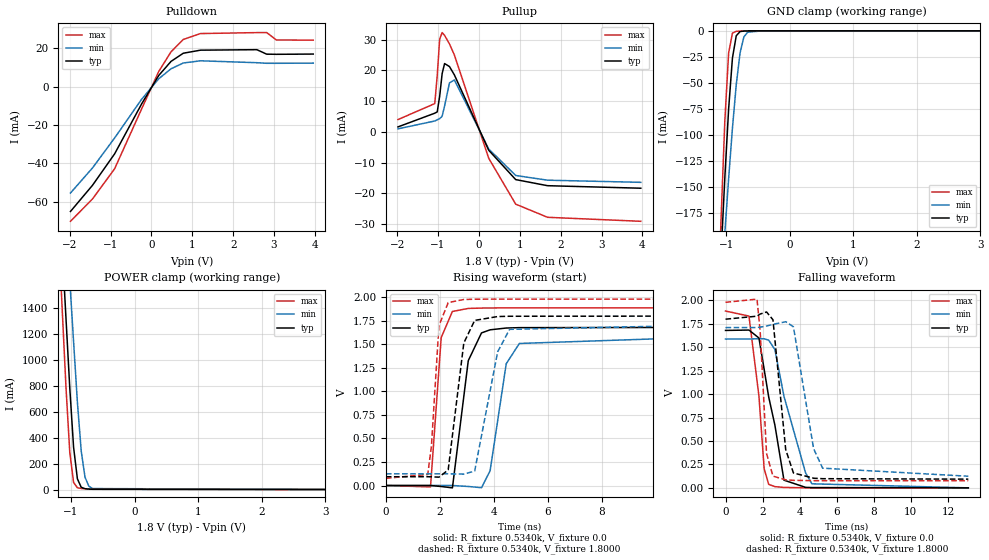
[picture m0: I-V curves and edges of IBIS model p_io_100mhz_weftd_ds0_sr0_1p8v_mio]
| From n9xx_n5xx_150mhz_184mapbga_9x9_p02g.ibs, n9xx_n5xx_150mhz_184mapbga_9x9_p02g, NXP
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[Model] p_io_100mhz_weftd_ds0_sr0_1p8v_mio
|   Model p_io_100mhz_weftd_ds0_sr0_1p8v_mio
| This model was characterised for following simulation conditions:
| External (pad) voltage:
|   - Typ: 1.8V,   - Min: 1.71V,   - Max: 1.98V
| Library cells for typ/min/max conditions are connected as defined below:
|  pad - External Pad
|  ipp_do_lv - Core Input
|  ipp_obe_lv - Output Buffer Enable
|  IOGC - NC
|  REFH3V3 - REFH3V3
|  REFL3V3 - REFL3V3
|  ZI - NC
|  abut_ncal_vddio[1] - vssio vddio vddio
|  abut_ncal_vddio[2] - vddio vddio vssio
|  abut_ncal_vddio[3] - vddio
|  abut_ncal_vddio[4] - vssio vddio vddio
|  abut_ncal_vddio[5] - vddio vddio vssio
|  abut_ncal_vddio[6] - vddio
|  abut_pcal_vddio[1] - vssio
|  abut_pcal_vddio[2] - vddio vssio vddio
|  abut_pcal_vddio[3] - vssio
|  abut_pcal_vddio[4] - vssio
|  abut_pcal_vddio[5] - vddio vssio vddio
|  abut_pcal_vddio[6] - vssio
|  ipp_do_1p8v - ipp_do_1p8v
|  ipp_dse_lv - 0
|  ipp_eftd_lv - NC
|  ipp_ina_mux_vddio - NC
|  ipp_ina_mux_vddio[0] - NC
|  ipp_ina_mux_vddio[1] - NC
|  ipp_ina_r0_vddio - NC
|  ipp_ina_r0a_vddio - NC
|  ipp_ina_r0b_vddio - NC
|  ipp_ina_r0c_vddio - NC
|  ipp_ina_r0d_vddio - NC
|  ipp_ina_r0e_vddio - NC
|  ipp_ina_r0f_vddio - NC
|  ipp_ina_r300_vddio - NC
|  ipp_ina_r300a_vddio - NC
|  ipp_ina_r300b_vddio - NC
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Model_type I/O
Polarity   Non-Inverting
Enable   Active-High
Vinl =   0.5400V
Vinh =   1.2600V
Vmeas =  0.9000V
Cref =   30.0000pF
Rref =   1.0000M
Vref =   1.8000V
C_comp   1.4209pF   1.3571pF   1.5007pF
|C_comp_pullup   0.7311pF   0.7578pF   0.7052pF
|C_comp_pulldown   0.6120pF   0.6628pF   0.5710pF
[Model Spec]
| variable   typ   min   max
Vinh   1.2600V   1.1970V   1.3860V
Vinl   0.5400V   0.5130V   0.5940V
[Temperature Range]   25.0000   0.1250k   -40.0000
[Voltage Range]   1.8000V   1.7100V   1.9800V
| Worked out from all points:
|   slope of the pulldown table from 0 to 0.27 V, typ, clamps not added: 32.1 ohm
|   slope of the pullup table from 0 to 0.27 V, typ, clamps not added: 40.9 ohm
|   GND clamp passes 1 mA (typ) near -0.78 V on its own axis
|   POWER clamp passes 1 mA (typ) near -0.56 V on its own axis
|   rising waveform, R_fixture 0.5340k, V_fixture 0.0: 20-80 % time 375ps typ, 478ps min, 240ps max; typ from 0 V to 1.68 V
|   rising waveform, R_fixture 0.5340k, V_fixture 1.8000: 20-80 % time 383ps typ, 516ps min, 234ps max; typ from 0.093 V to 1.8 V
|   falling waveform, R_fixture 0.5340k, V_fixture 0.0: 20-80 % time 874ps typ, 1.25ns min, 522ps max; typ from 1.68 V to 0 V
|   falling waveform, R_fixture 0.5340k, V_fixture 1.8000: 20-80 % time 429ps typ, 647ps min, 286ps max; typ from 1.8 V to 0.093 V
[Pulldown]
|Voltage   I(typ)   I(min)   I(max)
-1.98V    -65.1mA    -55.47mA   -70.23mA
-1.44V    -51.41mA   -42.35mA   -58.53mA
-900mV    -35.03mA   -26.74mA   -42.82mA
-240mV    -8.989mA   -6.551mA   -11.62mA
180mV     5.908mA    4.185mA    8mA
480mV     13.23mA    9.376mA    18.23mA
780mV     17.5mA     12.4mA     24.7mA
1.2V      19.1mA     13.55mA    27.77mA
2.58V     19.36mA    12.56mA    28.27mA
2.82V     17.02mA    12.25mA    28.29mA
3.06V     16.94mA    12.25mA    24.4mA
3.96V     17.07mA    12.34mA    24.35mA
[Pullup]
|Voltage   I(typ)   I(min)   I(max)
-1.98V    1.629mA    999.6uA    4.015mA
-1.08V    6.088mA    3.551mA    9.212mA
-1.02V    6.511mA    3.928mA    18.3mA
-960mV    11.61mA    4.321mA    30.17mA
-900mV    18.93mA    5.074mA    32.31mA
-840mV    22.23mA    8.425mA    31.4mA
-720mV    21.25mA    15.95mA    28.6mA
-600mV    18.53mA    16.91mA    25.01mA
240mV     -5.966mA   -5.551mA   -8.574mA
900mV     -15.51mA   -14.17mA   -23.49mA
1.68V     -17.49mA   -15.7mA    -27.77mA
3.96V     -18.31mA   -16.4mA    -29.07mA
[GND_clamp]
|Voltage   I(typ)   I(min)   I(max)
-1.98V    -1.543A    -1.201A    -2.023A
-1.14V    -295.8mA   -306.3mA   -290.9mA
-1.08V    -216.4mA   -249.6mA   -182.7mA
-1.02V    -141.5mA   -194.6mA   -86.96mA
-960mV    -75.17mA   -142.1mA   -21.27mA
-900mV    -26.1mA    -93.57mA   -2.196mA
-840mV    -4.74mA    -51.67mA   -453.8uA
-780mV    -724.6uA   -21.14mA   -264.4uA
-720mV    -210.5uA   -5.843mA   -181.4uA
-660mV    -110.6uA   -1.28mA    -117.6uA
-420mV    -5.355uA   -12.87uA   -3.465uA
3.96V     0A         0A         0A
[POWER_clamp]
|Voltage   I(typ)   I(min)   I(max)
-1.98V    9.578A     9.289A     10.07A
-1.2V     2.41A      3.038A     2.007A
-1.14V    1.864A     2.561A     1.396A
-1.08V    1.321A     2.084A     791.3mA
-1.02V    783mA      1.609A     287.7mA
-960mV    325.3mA    1.137A     54.76mA
-900mV    82.69mA    671.2mA    14.16mA
-840mV    18.08mA    297mA      8.834mA
-780mV    6.944mA    95.27mA    6.398mA
-720mV    4.174mA    26.01mA    4.41mA
-660mV    2.65mA     7.951mA    2.754mA
3.96V     0A         0A         0A
[Ramp]
| variable   typ   min   max
dV/dt_r  1.0081/0.3746n   0.9531/0.4784n   1.1320/0.2401n
dV/dt_f  1.0242/0.4289n   0.9515/0.6473n   1.1422/0.2863n
R_load = 0.5340k
[Rising Waveform]
R_fixture= 0.5340k
V_fixture= 0.0
V_fixture_min= 0.0
V_fixture_max= 0.0
|time   V(typ)   V(min)   V(max)
0s        469.4pV    172.1nV    14.64pV
1.655ns   101.7uV    -83.16uV   -15.11mV
2.051ns   -10.72mV   283.9uV    1.571V
2.467ns   -24.98mV   136.5uV    1.849V
3.054ns   1.326V     -10.16mV   1.881V
3.544ns   1.621V     -23.5mV    1.885V
3.864ns   1.654V     156.7mV    1.886V
4.461ns   1.673V     1.294V     1.887V
4.948ns   1.677V     1.509V     1.887V
13.1ns    1.68V      1.588V     1.887V
[Rising Waveform]
R_fixture= 0.5340k
V_fixture= 1.8000
V_fixture_min= 1.7100
V_fixture_max= 1.9800
|time   V(typ)   V(min)   V(max)
0s        93mV       124mV      76.32mV
1.553ns   93.25mV    123.9mV    117.6mV
1.688ns   92.31mV    123.9mV    416.6mV
1.968ns   88.84mV    124.2mV    1.699V
2.31ns    165.8mV    124.1mV    1.943V
2.889ns   1.514V     121mV      1.976V
3.292ns   1.754V     153.6mV    1.979V
4.142ns   1.795V     1.419V     1.98V
4.583ns   1.798V     1.659V     1.98V
13.1ns    1.8V       1.71V      1.98V
[Falling Waveform]
R_fixture= 0.5340k
V_fixture= 0.0
V_fixture_min= 0.0
V_fixture_max= 0.0
|time   V(typ)   V(min)   V(max)
0s        1.68V      1.588V     1.887V
1.266ns   1.684V     1.588V     1.833V
1.804ns   1.599V     1.592V     979.7mV
2.086ns   1.264V     1.591V     203.2mV
2.33ns    970.5mV    1.576V     37.35mV
2.664ns   670.3mV    1.476V     13.42mV
3.154ns   82.31mV    977.6mV    4.512mV
4.319ns   5.34mV     161mV      586.8uV
4.662ns   3.287mV    43.22mV    371.5uV
13.1ns    44.97uV    87.52uV    28.02uV
[Falling Waveform]
R_fixture= 0.5340k
V_fixture= 1.8000
V_fixture_min= 1.7100
V_fixture_max= 1.9800
|time   V(typ)   V(min)   V(max)
0s        1.8V       1.71V      1.98V
1.7ns     1.832V     1.711V     2.014V
1.872ns   1.855V     1.715V     1.669V
2.215ns   1.877V     1.727V     366.2mV
2.56ns    1.794V     1.745V     125.2mV
3.247ns   409.9mV    1.773V     85.73mV
3.664ns   159.1mV    1.719V     80.33mV
4.755ns   102.9mV    417.3mV    76.96mV
5.241ns   97.85mV    210.1mV    76.68mV
13.1ns    93.06mV    124.1mV    76.36mV
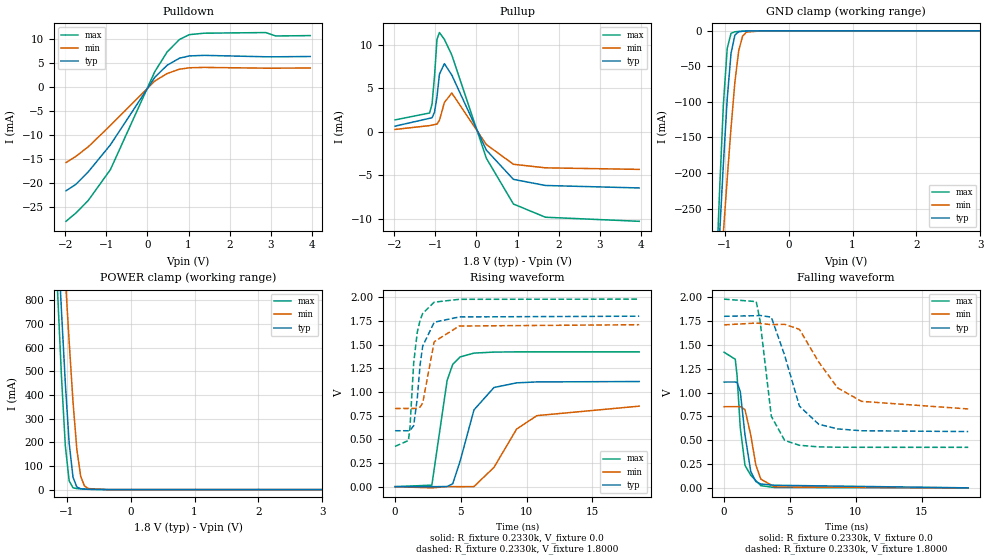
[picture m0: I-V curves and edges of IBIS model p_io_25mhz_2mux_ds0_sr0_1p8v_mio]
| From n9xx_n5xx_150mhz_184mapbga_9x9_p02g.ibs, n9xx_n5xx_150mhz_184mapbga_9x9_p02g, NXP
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[Model] p_io_25mhz_2mux_ds0_sr0_1p8v_mio
|   Model p_io_25mhz_2mux_ds0_sr0_1p8v_mio
| This model was characterised for following simulation conditions:
| External (pad) voltage:
|   - Typ: 1.8V,   - Min: 1.71V,   - Max: 1.98V
| Library cells for typ/min/max conditions are connected as defined below:
|  pad - External Pad
|  ipp_do_lv - Core Input
|  ipp_obe_lv - Output Buffer Enable
|  IOGC - NC
|  REFH3V3 - REFH3V3
|  REFL3V3 - REFL3V3
|  ZI - NC
|  abut_ncal_vddio[1] - vssio vddio vddio
|  abut_ncal_vddio[2] - vddio vddio vssio
|  abut_ncal_vddio[3] - vddio
|  abut_ncal_vddio[4] - vssio vddio vddio
|  abut_ncal_vddio[5] - vddio vddio vssio
|  abut_ncal_vddio[6] - vddio
|  abut_pcal_vddio[1] - vssio
|  abut_pcal_vddio[2] - vddio vssio vddio
|  abut_pcal_vddio[3] - vssio
|  abut_pcal_vddio[4] - vssio
|  abut_pcal_vddio[5] - vddio vssio vddio
|  abut_pcal_vddio[6] - vssio
|  ipp_do_1p8v - ipp_do_1p8v
|  ipp_dse_lv - 0
|  ipp_eftd_lv - NC
|  ipp_ina_mux_vddio - NC
|  ipp_ina_mux_vddio[0] - NC
|  ipp_ina_mux_vddio[1] - NC
|  ipp_ina_r0_vddio - NC
|  ipp_ina_r0a_vddio - NC
|  ipp_ina_r0b_vddio - NC
|  ipp_ina_r0c_vddio - NC
|  ipp_ina_r0d_vddio - NC
|  ipp_ina_r0e_vddio - NC
|  ipp_ina_r0f_vddio - NC
|  ipp_ina_r300_vddio - NC
|  ipp_ina_r300a_vddio - NC
|  ipp_ina_r300b_vddio - NC
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Model_type I/O
Polarity   Non-Inverting
Enable   Active-High
Vinl =   0.5400V
Vinh =   1.2600V
Vmeas =  0.9000V
Cref =   30.0000pF
Rref =   1.0000M
Vref =   1.8000V
C_comp   1.3067pF   1.2540pF   1.3694pF
|C_comp_pullup   0.5686pF   0.5978pF   0.5418pF
|C_comp_pulldown   0.6638pF   0.6956pF   0.6389pF
[Model Spec]
| variable   typ   min   max
Vinh   1.2600V   1.1970V   1.3860V
Vinl   0.5400V   0.5130V   0.5940V
[Temperature Range]   25.0000   0.1250k   -40.0000
[Voltage Range]   1.8000V   1.7100V   1.9800V
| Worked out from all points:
|   slope of the pulldown table from 0 to 0.27 V, typ, clamps not added: 93.6 ohm
|   slope of the pullup table from 0 to 0.27 V, typ, clamps not added: 116 ohm
|   GND clamp passes 1 mA (typ) near -0.75 V on its own axis
|   POWER clamp passes 1 mA (typ) near -0.63 V on its own axis
|   rising waveform, R_fixture 0.2330k, V_fixture 0.0: 20-80 % time 1.45ns typ, 2.43ns min, 833ps max; typ from 0 V to 1.11 V
|   rising waveform, R_fixture 0.2330k, V_fixture 1.8000: 20-80 % time 594ps typ, 656ps min, 564ps max; typ from 0.59 V to 1.8 V
|   falling waveform, R_fixture 0.2330k, V_fixture 0.0: 20-80 % time 571ps typ, 672ps min, 509ps max; typ from 1.11 V to 0 V
|   falling waveform, R_fixture 0.2330k, V_fixture 1.8000: 20-80 % time 1.51ns typ, 2.64ns min, 803ps max; typ from 1.8 V to 0.591 V
[Pulldown]
|Voltage   I(typ)   I(min)   I(max)
-1.98V    -21.59mA   -15.72mA   -27.94mA
-1.74V    -20.25mA   -14.42mA   -26.22mA
-1.44V    -17.66mA   -12.45mA   -23.61mA
-900mV    -12.03mA   -7.992mA   -17.18mA
180mV     2.026mA    1.252mA    3.209mA
480mV     4.533mA    2.805mA    7.304mA
780mV     5.999mA    3.712mA    9.89mA
1.02V     6.468mA    4.005mA    10.9mA
1.38V     6.587mA    4.078mA    11.2mA
2.88V     6.293mA    3.922mA    11.33mA
3.12V     6.289mA    3.924mA    10.62mA
3.96V     6.35mA     3.959mA    10.7mA
[Pullup]
|Voltage   I(typ)   I(min)   I(max)
-1.98V    644.9uA    266.3uA    1.361mA
-1.14V    1.542mA    707.2uA    2.153mA
-1.08V    1.604mA    764.5uA    3.171mA
-1.02V    2.234mA    824.1uA    6.358mA
-960mV    4.021mA    885.3uA    10.59mA
-900mV    6.607mA    1.315mA    11.37mA
-780mV    7.807mA    3.354mA    10.59mA
-600mV    6.505mA    4.443mA    8.805mA
240mV     -2.097mA   -1.459mA   -3.022mA
900mV     -5.454mA   -3.726mA   -8.28mA
1.68V     -6.156mA   -4.132mA   -9.795mA
3.96V     -6.438mA   -4.31mA    -10.26mA
[GND_clamp]
|Voltage   I(typ)   I(min)   I(max)
-1.98V    -2A        -1.65A     -2.499A
-1.14V    -394mA     -441.5mA   -363.8mA
-1.08V    -288.3mA   -361.7mA   -226.5mA
-1.02V    -187.2mA   -283.6mA   -103.8mA
-960mV    -95.65mA   -208mA     -24.73mA
-900mV    -31.48mA   -136.2mA   -3.446mA
-840mV    -6.013mA   -72.18mA   -1.335mA
-780mV    -1.302mA   -27.91mA   -907.3uA
-720mV    -579.6uA   -7.635mA   -620.4uA
-660mV    -347.7uA   -1.81mA    -390uA
-420mV    -12.74uA   -30.23uA   -7.287uA
3.96V     0A         0A         0A
[POWER_clamp]
|Voltage   I(typ)   I(min)   I(max)
-1.98V    5.618A     5.349A     6.084A
-1.14V    1.071A     1.443A     829.6mA
-1.08V    754.2mA    1.168A     476.4mA
-1.02V    449mA      895.6mA    184.6mA
-960mV    195.8mA    625.5mA    36.76mA
-900mV    52.43mA    371.1mA    7.779mA
-840mV    10.73mA    170.2mA    4.41mA
-780mV    3.609mA    56.22mA    3.161mA
-720mV    2.066mA    15.04mA    2.177mA
-660mV    1.299mA    4.297mA    1.362mA
-360mV    4.834uA    27.3uA     1.2uA
3.96V     0A         0A         0A
[Ramp]
| variable   typ   min   max
dV/dt_r  0.6658/1.4492n   0.5100/2.4251n   0.8537/0.8330n
dV/dt_f  0.7257/1.5102n   0.5293/2.6446n   0.9328/0.8032n
R_load = 0.2330k
[Rising Waveform]
R_fixture= 0.2330k
V_fixture= 0.0
V_fixture_min= 0.0
V_fixture_max= 0.0
|time   V(typ)   V(min)   V(max)
0s        586.1pV    202.5nV    16.24pV
2.795ns   -85.97uV   -12.58mV   16.06mV
3.955ns   1.317mV    419.6uV    1.121V
4.382ns   30.46mV    829.6uV    1.291V
4.948ns   272mV      154.2uV    1.37V
5.996ns   810.5mV    1.17mV     1.41V
7.517ns   1.047V     204.1mV    1.421V
9.234ns   1.096V     607.6mV    1.423V
10.78ns   1.106V     750.1mV    1.423V
18.55ns   1.11V      850.1mV    1.423V
[Rising Waveform]
R_fixture= 0.2330k
V_fixture= 1.8000
V_fixture_min= 1.7100
V_fixture_max= 1.9800
|time   V(typ)   V(min)   V(max)
0s        590.5mV    825.5mV    425.3mV
1.015ns   590.4mV    825.6mV    487.4mV
1.131ns   591.3mV    825.6mV    619.4mV
1.413ns   643.9mV    825.6mV    1.303V
1.687ns   930.3mV    826.4mV    1.629V
1.906ns   1.292V     841.7mV    1.759V
2.101ns   1.484V     883.5mV    1.829V
2.974ns   1.736V     1.53V      1.948V
4.88ns    1.792V     1.696V     1.978V
18.55ns   1.8V       1.71V      1.98V
[Falling Waveform]
R_fixture= 0.2330k
V_fixture= 0.0
V_fixture_min= 0.0
V_fixture_max= 0.0
|time   V(typ)   V(min)   V(max)
0s        1.11V      851.6mV    1.423V
851.4ps   1.111V     851.6mV    1.349V
987.8ps   1.105V     851.6mV    1.177V
1.23ns    1.012V     853.3mV    632.6mV
1.588ns   556.7mV    821.3mV    237mV
2.028ns   171.6mV    553.9mV    131.8mV
2.413ns   66.38mV    239.2mV    76.44mV
2.793ns   40.27mV    91.14mV    23mV
3.824ns   27.36mV    10.55mV    3.971mV
18.55ns   311.9nV    11.36uV    55.71nV
[Falling Waveform]
R_fixture= 0.2330k
V_fixture= 1.8000
V_fixture_min= 1.7100
V_fixture_max= 1.9800
|time   V(typ)   V(min)   V(max)
0s        1.8V       1.71V      1.98V
2.443ns   1.806V     1.729V     1.954V
2.729ns   1.809V     1.725V     1.758V
3.59ns    1.791V     1.712V     751mV
4.601ns   1.391V     1.716V     498.2mV
5.726ns   857.5mV    1.663V     446.5mV
7.189ns   667.1mV    1.32V      429.9mV
8.633ns   618.5mV    1.048V     426.5mV
10.45ns   599mV      907.3mV    425.5mV
18.55ns   590.6mV    827.9mV    425.3mV
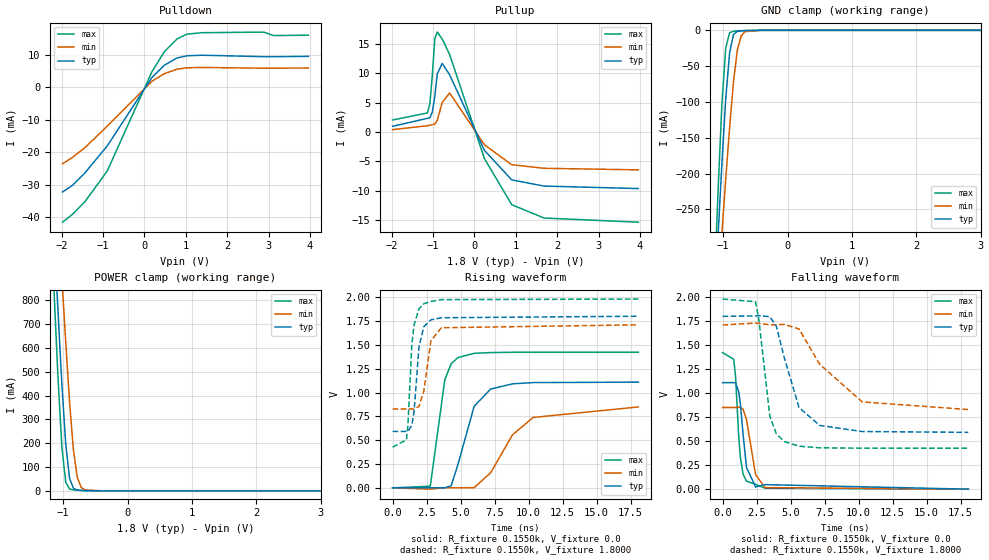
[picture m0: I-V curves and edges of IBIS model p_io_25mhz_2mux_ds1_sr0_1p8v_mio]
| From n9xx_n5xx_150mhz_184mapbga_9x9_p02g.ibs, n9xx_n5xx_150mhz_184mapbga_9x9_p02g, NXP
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[Model] p_io_25mhz_2mux_ds1_sr0_1p8v_mio
|   Model p_io_25mhz_2mux_ds1_sr0_1p8v_mio
| This model was characterised for following simulation conditions:
| External (pad) voltage:
|   - Typ: 1.8V,   - Min: 1.71V,   - Max: 1.98V
| Library cells for typ/min/max conditions are connected as defined below:
|  pad - External Pad
|  ipp_do_lv - Core Input
|  ipp_obe_lv - Output Buffer Enable
|  IOGC - NC
|  REFH3V3 - REFH3V3
|  REFL3V3 - REFL3V3
|  ZI - NC
|  abut_ncal_vddio[1] - vssio vddio vddio
|  abut_ncal_vddio[2] - vddio vddio vssio
|  abut_ncal_vddio[3] - vddio
|  abut_ncal_vddio[4] - vssio vddio vddio
|  abut_ncal_vddio[5] - vddio vddio vssio
|  abut_ncal_vddio[6] - vddio
|  abut_pcal_vddio[1] - vssio
|  abut_pcal_vddio[2] - vddio vssio vddio
|  abut_pcal_vddio[3] - vssio
|  abut_pcal_vddio[4] - vssio
|  abut_pcal_vddio[5] - vddio vssio vddio
|  abut_pcal_vddio[6] - vssio
|  ipp_do_1p8v - ipp_do_1p8v
|  ipp_dse_lv - vdd_lv
|  ipp_eftd_lv - NC
|  ipp_ina_mux_vddio - NC
|  ipp_ina_mux_vddio[0] - NC
|  ipp_ina_mux_vddio[1] - NC
|  ipp_ina_r0_vddio - NC
|  ipp_ina_r0a_vddio - NC
|  ipp_ina_r0b_vddio - NC
|  ipp_ina_r0c_vddio - NC
|  ipp_ina_r0d_vddio - NC
|  ipp_ina_r0e_vddio - NC
|  ipp_ina_r0f_vddio - NC
|  ipp_ina_r300_vddio - NC
|  ipp_ina_r300a_vddio - NC
|  ipp_ina_r300b_vddio - NC
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Model_type I/O
Polarity   Non-Inverting
Enable   Active-High
Vinl =   0.5400V
Vinh =   1.2600V
Vmeas =  0.9000V
Cref =   30.0000pF
Rref =   1.0000M
Vref =   1.8000V
C_comp   1.3067pF   1.2540pF   1.3694pF
|C_comp_pullup   0.5683pF   0.5975pF   0.5415pF
|C_comp_pulldown   0.6642pF   0.6959pF   0.6393pF
[Model Spec]
| variable   typ   min   max
Vinh   1.2600V   1.1970V   1.3860V
Vinl   0.5400V   0.5130V   0.5940V
[Temperature Range]   25.0000   0.1250k   -40.0000
[Voltage Range]   1.8000V   1.7100V   1.9800V
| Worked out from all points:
|   slope of the pulldown table from 0 to 0.27 V, typ, clamps not added: 62.4 ohm
|   slope of the pullup table from 0 to 0.27 V, typ, clamps not added: 77.5 ohm
|   GND clamp passes 1 mA (typ) near -0.75 V on its own axis
|   POWER clamp passes 1 mA (typ) near -0.63 V on its own axis
|   rising waveform, R_fixture 0.1550k, V_fixture 0.0: 20-80 % time 1.35ns typ, 2.38ns min, 760ps max; typ from 0 V to 1.11 V
|   rising waveform, R_fixture 0.1550k, V_fixture 1.8000: 20-80 % time 422ps typ, 518ps min, 382ps max; typ from 0.592 V to 1.8 V
|   falling waveform, R_fixture 0.1550k, V_fixture 0.0: 20-80 % time 453ps typ, 574ps min, 375ps max; typ from 1.11 V to 0 V
|   falling waveform, R_fixture 0.1550k, V_fixture 1.8000: 20-80 % time 1.46ns typ, 2.58ns min, 755ps max; typ from 1.8 V to 0.592 V
[Pulldown]
|Voltage   I(typ)   I(min)   I(max)
-1.98V    -32.19mA   -23.51mA   -41.49mA
-1.74V    -30.15mA   -21.53mA   -39.06mA
-1.44V    -26.33mA   -18.56mA   -35.19mA
-900mV    -18.01mA   -11.95mA   -25.73mA
180mV     3.037mA    1.878mA    4.81mA
480mV     6.798mA    4.207mA    10.95mA
780mV     8.998mA    5.569mA    14.83mA
1.02V     9.703mA    6.009mA    16.35mA
1.38V     9.882mA    6.118mA    16.81mA
2.88V     9.44mA     5.884mA    17mA
3.12V     9.433mA    5.887mA    15.93mA
3.96V     9.527mA    5.94mA     16.05mA
[Pullup]
|Voltage   I(typ)   I(min)   I(max)
-1.98V    966.3uA    399.3uA    2.044mA
-1.14V    2.321mA    1.063mA    3.243mA
-1.08V    2.416mA    1.15mA     4.764mA
-1.02V    3.358mA    1.24mA     9.557mA
-960mV    6.04mA     1.332mA    15.9mA
-900mV    9.92mA     1.974mA    17.06mA
-780mV    11.71mA    5.034mA    15.89mA
-600mV    9.758mA    6.666mA    13.21mA
240mV     -3.146mA   -2.189mA   -4.533mA
900mV     -8.184mA   -5.592mA   -12.42mA
1.68V     -9.239mA   -6.201mA   -14.7mA
3.96V     -9.667mA   -6.471mA   -15.41mA
[GND_clamp]
|Voltage   I(typ)   I(min)   I(max)
-1.98V    -2A        -1.65A     -2.499A
-1.14V    -394mA     -441.5mA   -363.8mA
-1.08V    -288.3mA   -361.7mA   -226.5mA
-1.02V    -187.2mA   -283.6mA   -103.8mA
-960mV    -95.65mA   -208mA     -24.73mA
-900mV    -31.48mA   -136.2mA   -3.446mA
-840mV    -6.013mA   -72.18mA   -1.335mA
-780mV    -1.302mA   -27.91mA   -907.3uA
-720mV    -579.6uA   -7.636mA   -620.4uA
-660mV    -347.7uA   -1.81mA    -390uA
-420mV    -12.74uA   -30.28uA   -7.287uA
3.96V     0A         0A         0A
[POWER_clamp]
|Voltage   I(typ)   I(min)   I(max)
-1.98V    5.618A     5.349A     6.084A
-1.14V    1.071A     1.443A     829.6mA
-1.08V    754.2mA    1.168A     476.4mA
-1.02V    449mA      895.6mA    184.6mA
-960mV    195.8mA    625.5mA    36.76mA
-900mV    52.43mA    371.1mA    7.779mA
-840mV    10.73mA    170.2mA    4.41mA
-780mV    3.609mA    56.22mA    3.161mA
-720mV    2.066mA    15.04mA    2.177mA
-660mV    1.299mA    4.297mA    1.362mA
-360mV    4.834uA    27.3uA     1.2uA
3.96V     0A         0A         0A
[Ramp]
| variable   typ   min   max
dV/dt_r  0.6652/1.3475n   0.5092/2.3844n   0.8531/0.7600n
dV/dt_f  0.7249/1.4571n   0.5285/2.5847n   0.9321/0.7551n
R_load = 0.1550k
[Rising Waveform]
R_fixture= 0.1550k
V_fixture= 0.0
V_fixture_min= 0.0
V_fixture_max= 0.0
|time   V(typ)   V(min)   V(max)
0s        408.8pV    135.5nV    11.61pV
2.774ns   1.162mV    -13.58mV   18.06mV
3.836ns   232.2uV    936.4uV    1.132V
4.306ns   22.02mV    1.123mV    1.302V
4.813ns   249.4mV    545.3uV    1.367V
5.996ns   855.7mV    2.319mV    1.411V
7.206ns   1.036V     158mV      1.419V
8.808ns   1.091V     555.5mV    1.422V
10.33ns   1.104V     738.5mV    1.422V
18.06ns   1.109V     848.7mV    1.422V
[Rising Waveform]
R_fixture= 0.1550k
V_fixture= 1.8000
V_fixture_min= 1.7100
V_fixture_max= 1.9800
|time   V(typ)   V(min)   V(max)
0s        591.8mV    826.8mV    426.5mV
1.021ns   591.5mV    826.8mV    503.4mV
1.129ns   592.9mV    826.8mV    657.1mV
1.413ns   655.9mV    826.8mV    1.495V
1.578ns   797.1mV    826.6mV    1.707V
1.944ns   1.482V     854.9mV    1.879V
2.298ns   1.69V      1.015V     1.931V
2.82ns    1.762V     1.544V     1.955V
3.586ns   1.784V     1.679V     1.974V
18.06ns   1.8V       1.71V      1.98V
[Falling Waveform]
R_fixture= 0.1550k
V_fixture= 0.0
V_fixture_min= 0.0
V_fixture_max= 0.0
|time   V(typ)   V(min)   V(max)
0s        1.109V     850.6mV    1.422V
816.9ps   1.11V      850.5mV    1.353V
951.9ps   1.107V     850.6mV    1.181V
1.186ns   1.016V     852.9mV    551.3mV
1.305ns   893.8mV    853.3mV    335.1mV
1.511ns   566.3mV    830.2mV    155.2mV
1.759ns   225.8mV    724.5mV    83.02mV
2.428ns   23.3mV     150mV      50.47mV
3.117ns   47.51mV    16.51mV    9.609mV
18.06ns   302.2nV    12.16uV    23.95nV
[Falling Waveform]
R_fixture= 0.1550k
V_fixture= 1.8000
V_fixture_min= 1.7100
V_fixture_max= 1.9800
|time   V(typ)   V(min)   V(max)
0s        1.8V       1.71V      1.98V
2.42ns    1.804V     1.73V      1.953V
2.668ns   1.808V     1.726V     1.766V
3.471ns   1.796V     1.712V     759.9mV
3.948ns   1.698V     1.713V     576.3mV
4.549ns   1.363V     1.716V     495.4mV
5.62ns    850.1mV    1.668V     447.4mV
7.136ns   663.5mV    1.301V     430.8mV
10.26ns   600.2mV    909.1mV    426.7mV
18.06ns   591.8mV    829.2mV    426.5mV
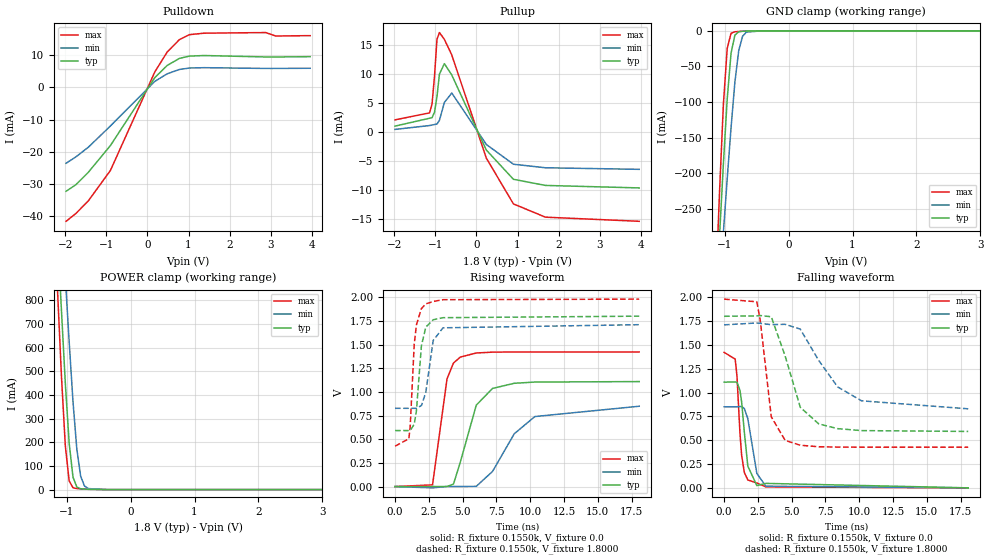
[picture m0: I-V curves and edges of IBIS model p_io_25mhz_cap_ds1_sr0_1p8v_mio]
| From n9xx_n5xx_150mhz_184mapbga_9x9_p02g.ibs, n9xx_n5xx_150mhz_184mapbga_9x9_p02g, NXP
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[Model] p_io_25mhz_cap_ds1_sr0_1p8v_mio
|   Model p_io_25mhz_cap_ds1_sr0_1p8v_mio
| This model was characterised for following simulation conditions:
| External (pad) voltage:
|   - Typ: 1.8V,   - Min: 1.71V,   - Max: 1.98V
| Library cells for typ/min/max conditions are connected as defined below:
|  pad - External Pad
|  ipp_do_lv - Core Input
|  ipp_obe_lv - Output Buffer Enable
|  IOGC - NC
|  REFH3V3 - REFH3V3
|  REFL3V3 - REFL3V3
|  ZI - NC
|  abut_ncal_vddio[1] - vssio vddio vddio
|  abut_ncal_vddio[2] - vddio vddio vssio
|  abut_ncal_vddio[3] - vddio
|  abut_ncal_vddio[4] - vssio vddio vddio
|  abut_ncal_vddio[5] - vddio vddio vssio
|  abut_ncal_vddio[6] - vddio
|  abut_pcal_vddio[1] - vssio
|  abut_pcal_vddio[2] - vddio vssio vddio
|  abut_pcal_vddio[3] - vssio
|  abut_pcal_vddio[4] - vssio
|  abut_pcal_vddio[5] - vddio vssio vddio
|  abut_pcal_vddio[6] - vssio
|  ipp_do_1p8v - ipp_do_1p8v
|  ipp_dse_lv - vdd_lv
|  ipp_eftd_lv - NC
|  ipp_ina_mux_vddio - NC
|  ipp_ina_mux_vddio[0] - NC
|  ipp_ina_mux_vddio[1] - NC
|  ipp_ina_r0_vddio - NC
|  ipp_ina_r0a_vddio - NC
|  ipp_ina_r0b_vddio - NC
|  ipp_ina_r0c_vddio - NC
|  ipp_ina_r0d_vddio - NC
|  ipp_ina_r0e_vddio - NC
|  ipp_ina_r0f_vddio - NC
|  ipp_ina_r300_vddio - NC
|  ipp_ina_r300a_vddio - NC
|  ipp_ina_r300b_vddio - NC
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Model_type I/O
Polarity   Non-Inverting
Enable   Active-High
Vinl =   0.5400V
Vinh =   1.2600V
Vmeas =  0.9000V
Cref =   30.0000pF
Rref =   1.0000M
Vref =   1.8000V
C_comp   1.3068pF   1.2541pF   1.3694pF
|C_comp_pullup   0.5693pF   0.5985pF   0.5425pF
|C_comp_pulldown   0.6508pF   0.6825pF   0.6258pF
[Model Spec]
| variable   typ   min   max
Vinh   1.2600V   1.1970V   1.3860V
Vinl   0.5400V   0.5130V   0.5940V
[Temperature Range]   25.0000   0.1250k   -40.0000
[Voltage Range]   1.8000V   1.7100V   1.9800V
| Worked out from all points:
|   slope of the pulldown table from 0 to 0.27 V, typ, clamps not added: 62.4 ohm
|   slope of the pullup table from 0 to 0.27 V, typ, clamps not added: 77.5 ohm
|   GND clamp passes 1 mA (typ) near -0.76 V on its own axis
|   POWER clamp passes 1 mA (typ) near -0.63 V on its own axis
|   rising waveform, R_fixture 0.1550k, V_fixture 0.0: 20-80 % time 1.35ns typ, 2.38ns min, 759ps max; typ from 0 V to 1.11 V
|   rising waveform, R_fixture 0.1550k, V_fixture 1.8000: 20-80 % time 423ps typ, 518ps min, 382ps max; typ from 0.592 V to 1.8 V
|   falling waveform, R_fixture 0.1550k, V_fixture 0.0: 20-80 % time 453ps typ, 574ps min, 375ps max; typ from 1.11 V to 0 V
|   falling waveform, R_fixture 0.1550k, V_fixture 1.8000: 20-80 % time 1.46ns typ, 2.58ns min, 755ps max; typ from 1.8 V to 0.592 V
[Pulldown]
|Voltage   I(typ)   I(min)   I(max)
-1.98V    -32.19mA   -23.51mA   -41.49mA
-1.74V    -30.15mA   -21.53mA   -39.06mA
-1.44V    -26.34mA   -18.56mA   -35.19mA
-900mV    -18.01mA   -11.95mA   -25.73mA
180mV     3.037mA    1.878mA    4.81mA
480mV     6.798mA    4.207mA    10.95mA
780mV     8.998mA    5.569mA    14.83mA
1.02V     9.704mA    6.009mA    16.35mA
1.38V     9.882mA    6.119mA    16.81mA
2.88V     9.44mA     5.884mA    17mA
3.12V     9.433mA    5.887mA    15.93mA
3.96V     9.528mA    5.94mA     16.05mA
[Pullup]
|Voltage   I(typ)   I(min)   I(max)
-1.98V    966.2uA    399.3uA    2.044mA
-1.14V    2.321mA    1.063mA    3.243mA
-1.08V    2.416mA    1.15mA     4.764mA
-1.02V    3.358mA    1.24mA     9.557mA
-960mV    6.04mA     1.332mA    15.9mA
-900mV    9.92mA     1.974mA    17.06mA
-780mV    11.71mA    5.034mA    15.89mA
-600mV    9.758mA    6.666mA    13.21mA
240mV     -3.146mA   -2.189mA   -4.533mA
900mV     -8.184mA   -5.592mA   -12.42mA
1.68V     -9.239mA   -6.201mA   -14.7mA
3.96V     -9.667mA   -6.471mA   -15.41mA
[GND_clamp]
|Voltage   I(typ)   I(min)   I(max)
-1.98V    -2A        -1.65A     -2.499A
-1.14V    -394mA     -441.5mA   -363.8mA
-1.08V    -288.3mA   -361.7mA   -226.5mA
-1.02V    -187.2mA   -283.6mA   -103.8mA
-960mV    -95.64mA   -207.9mA   -24.71mA
-900mV    -31.47mA   -136.2mA   -3.431mA
-840mV    -6.005mA   -72.18mA   -1.326mA
-780mV    -1.297mA   -27.91mA   -902.8uA
-720mV    -576.7uA   -7.632mA   -619.4uA
-660mV    -346.6uA   -1.808mA   -391.2uA
-420mV    -13.9uA    -31.16uA   -8.588uA
3.96V     0A         0A         0A
[POWER_clamp]
|Voltage   I(typ)   I(min)   I(max)
-1.98V    5.618A     5.349A     6.084A
-1.14V    1.071A     1.443A     829.6mA
-1.08V    754.2mA    1.168A     476.4mA
-1.02V    449mA      895.6mA    184.6mA
-960mV    195.8mA    625.5mA    36.79mA
-900mV    52.44mA    371.1mA    7.808mA
-840mV    10.74mA    170.2mA    4.435mA
-780mV    3.619mA    56.22mA    3.182mA
-720mV    2.074mA    15.04mA    2.195mA
-660mV    1.306mA    4.299mA    1.376mA
-360mV    5.079uA    27.62uA    1.341uA
3.96V     0A         0A         0A
[Ramp]
| variable   typ   min   max
dV/dt_r  0.6652/1.3478n   0.5092/2.3844n   0.8531/0.7592n
dV/dt_f  0.7249/1.4569n   0.5285/2.5821n   0.9321/0.7550n
R_load = 0.1550k
[Rising Waveform]
R_fixture= 0.1550k
V_fixture= 0.0
V_fixture_min= 0.0
V_fixture_max= 0.0
|time   V(typ)   V(min)   V(max)
0s        440.2pV    137.5nV    11.95pV
2.772ns   1.146mV    -13.59mV   17.83mV
3.844ns   423uV      947.4uV    1.138V
4.323ns   26.58mV    1.112mV    1.305V
4.828ns   258.5mV    522.2uV    1.368V
6.008ns   860.2mV    2.482mV    1.411V
7.212ns   1.037V     160mV      1.42V
8.814ns   1.091V     557.1mV    1.422V
10.34ns   1.104V     739.6mV    1.422V
18.06ns   1.109V     848.7mV    1.422V
[Rising Waveform]
R_fixture= 0.1550k
V_fixture= 1.8000
V_fixture_min= 1.7100
V_fixture_max= 1.9800
|time   V(typ)   V(min)   V(max)
0s        591.8mV    826.8mV    426.4mV
1.024ns   591.5mV    826.8mV    505.5mV
1.122ns   592.5mV    826.8mV    638.2mV
1.419ns   658.4mV    826.8mV    1.505V
1.581ns   800.8mV    826.6mV    1.709V
1.948ns   1.485V     855.5mV    1.88V
2.277ns   1.685V     996.3mV    1.93V
2.821ns   1.762V     1.544V     1.955V
3.55ns    1.784V     1.677V     1.974V
18.06ns   1.8V       1.71V      1.98V
[Falling Waveform]
R_fixture= 0.1550k
V_fixture= 0.0
V_fixture_min= 0.0
V_fixture_max= 0.0
|time   V(typ)   V(min)   V(max)
0s        1.109V     850.6mV    1.422V
819.8ps   1.111V     850.5mV    1.351V
954.8ps   1.107V     850.7mV    1.174V
1.174ns   1.023V     852.7mV    577.9mV
1.299ns   900.8mV    853.4mV    342.6mV
1.499ns   584.8mV    832.5mV    161.4mV
1.756ns   228.2mV    725.8mV    83.12mV
2.427ns   23.3mV     150mV      50.69mV
3.093ns   46.97mV    17.54mV    10.01mV
18.06ns   302.3nV    12.16uV    23.9nV
[Falling Waveform]
R_fixture= 0.1550k
V_fixture= 1.8000
V_fixture_min= 1.7100
V_fixture_max= 1.9800
|time   V(typ)   V(min)   V(max)
0s        1.8V       1.71V      1.98V
2.422ns   1.804V     1.73V      1.952V
2.67ns    1.808V     1.726V     1.764V
3.492ns   1.795V     1.712V     745.3mV
4.518ns   1.383V     1.716V     498.1mV
5.638ns   845.2mV    1.665V     447.1mV
6.995ns   671.5mV    1.338V     431.4mV
8.401ns   621.1mV    1.059V     427.7mV
10.17ns   600.7mV    913.2mV    426.7mV
18.06ns   591.8mV    829.2mV    426.5mV
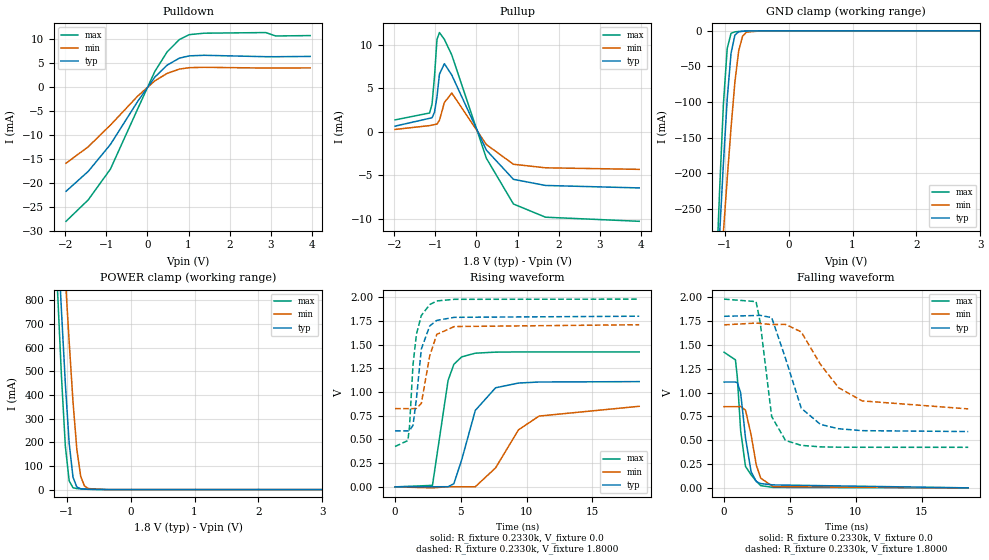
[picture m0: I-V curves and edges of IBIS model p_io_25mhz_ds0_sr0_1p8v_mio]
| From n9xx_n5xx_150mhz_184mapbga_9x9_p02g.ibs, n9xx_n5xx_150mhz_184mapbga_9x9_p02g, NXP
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[Model] p_io_25mhz_ds0_sr0_1p8v_mio
|   Model p_io_25mhz_ds0_sr0_1p8v_mio
| This model was characterised for following simulation conditions:
| External (pad) voltage:
|   - Typ: 1.8V,   - Min: 1.71V,   - Max: 1.98V
| Library cells for typ/min/max conditions are connected as defined below:
|  pad - External Pad
|  ipp_do_lv - Core Input
|  ipp_obe_lv - Output Buffer Enable
|  IOGC - NC
|  REFH3V3 - REFH3V3
|  REFL3V3 - REFL3V3
|  ZI - NC
|  abut_ncal_vddio[1] - vssio vddio vddio
|  abut_ncal_vddio[2] - vddio vddio vssio
|  abut_ncal_vddio[3] - vddio
|  abut_ncal_vddio[4] - vssio vddio vddio
|  abut_ncal_vddio[5] - vddio vddio vssio
|  abut_ncal_vddio[6] - vddio
|  abut_pcal_vddio[1] - vssio
|  abut_pcal_vddio[2] - vddio vssio vddio
|  abut_pcal_vddio[3] - vssio
|  abut_pcal_vddio[4] - vssio
|  abut_pcal_vddio[5] - vddio vssio vddio
|  abut_pcal_vddio[6] - vssio
|  ipp_do_1p8v - ipp_do_1p8v
|  ipp_dse_lv - 0
|  ipp_eftd_lv - NC
|  ipp_ina_mux_vddio - NC
|  ipp_ina_mux_vddio[0] - NC
|  ipp_ina_mux_vddio[1] - NC
|  ipp_ina_r0_vddio - NC
|  ipp_ina_r0a_vddio - NC
|  ipp_ina_r0b_vddio - NC
|  ipp_ina_r0c_vddio - NC
|  ipp_ina_r0d_vddio - NC
|  ipp_ina_r0e_vddio - NC
|  ipp_ina_r0f_vddio - NC
|  ipp_ina_r300_vddio - NC
|  ipp_ina_r300a_vddio - NC
|  ipp_ina_r300b_vddio - NC
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Model_type I/O
Polarity   Non-Inverting
Enable   Active-High
Vinl =   0.5400V
Vinh =   1.2600V
Vmeas =  0.9000V
Cref =   30.0000pF
Rref =   1.0000M
Vref =   1.8000V
C_comp   1.3069pF   1.2545pF   1.3693pF
|C_comp_pullup   0.5683pF   0.5977pF   0.5415pF
|C_comp_pulldown   0.6468pF   0.6780pF   0.6223pF
[Model Spec]
| variable   typ   min   max
Vinh   1.2600V   1.1970V   1.3860V
Vinl   0.5400V   0.5130V   0.5940V
[Temperature Range]   25.0000   0.1250k   -40.0000
[Voltage Range]   1.8000V   1.7100V   1.9800V
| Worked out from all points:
|   slope of the pulldown table from 0 to 0.27 V, typ, clamps not added: 93.6 ohm
|   slope of the pullup table from 0 to 0.27 V, typ, clamps not added: 116 ohm
|   GND clamp passes 1 mA (typ) near -0.75 V on its own axis
|   POWER clamp passes 1 mA (typ) near -0.63 V on its own axis
|   rising waveform, R_fixture 0.2330k, V_fixture 0.0: 20-80 % time 1.48ns typ, 2.49ns min, 851ps max; typ from 0 V to 1.11 V
|   rising waveform, R_fixture 0.2330k, V_fixture 1.8000: 20-80 % time 591ps typ, 654ps min, 568ps max; typ from 0.591 V to 1.8 V
|   falling waveform, R_fixture 0.2330k, V_fixture 0.0: 20-80 % time 576ps typ, 681ps min, 511ps max; typ from 1.11 V to 0 V
|   falling waveform, R_fixture 0.2330k, V_fixture 1.8000: 20-80 % time 1.57ns typ, 2.75ns min, 829ps max; typ from 1.8 V to 0.591 V
[Pulldown]
|Voltage   I(typ)   I(min)   I(max)
-1.98V    -21.81mA   -15.95mA   -28.07mA
-1.44V    -17.65mA   -12.51mA   -23.6mA
-900mV    -12.03mA   -7.99mA    -17.17mA
-240mV    -3.083mA   -1.961mA   -4.663mA
180mV     2.025mA    1.252mA    3.208mA
480mV     4.532mA    2.805mA    7.302mA
780mV     5.997mA    3.712mA    9.887mA
1.02V     6.467mA    4.004mA    10.9mA
1.38V     6.586mA    4.077mA    11.2mA
2.88V     6.292mA    3.922mA    11.33mA
3.12V     6.287mA    3.924mA    10.62mA
3.96V     6.35mA     3.959mA    10.7mA
[Pullup]
|Voltage   I(typ)   I(min)   I(max)
-1.98V    645.6uA    266.4uA    1.363mA
-1.14V    1.543mA    707.6uA    2.155mA
-1.08V    1.605mA    764.9uA    3.173mA
-1.02V    2.235mA    824.6uA    6.361mA
-960mV    4.023mA    885.7uA    10.59mA
-900mV    6.61mA     1.315mA    11.38mA
-780mV    7.81mA     3.355mA    10.6mA
-600mV    6.507mA    4.444mA    8.808mA
240mV     -2.097mA   -1.459mA   -3.023mA
900mV     -5.456mA   -3.727mA   -8.283mA
1.68V     -6.158mA   -4.133mA   -9.8mA
3.96V     -6.441mA   -4.311mA   -10.27mA
[GND_clamp]
|Voltage   I(typ)   I(min)   I(max)
-1.98V    -1.998A    -1.645A    -2.498A
-1.14V    -394mA     -441.4mA   -363.8mA
-1.08V    -288.3mA   -361.7mA   -226.5mA
-1.02V    -187.2mA   -283.6mA   -103.9mA
-960mV    -95.66mA   -207.9mA   -24.8mA
-900mV    -31.51mA   -136.2mA   -3.52mA
-840mV    -6.042mA   -72.18mA   -1.393mA
-780mV    -1.326mA   -27.91mA   -950.1uA
-720mV    -597.6uA   -7.636mA   -651.3uA
-660mV    -360.6uA   -1.814mA   -411.4uA
-420mV    -15.1uA    -32.81uA   -9.558uA
3.96V     0A         0A         0A
[POWER_clamp]
|Voltage   I(typ)   I(min)   I(max)
-1.98V    5.618A     5.349A     6.084A
-1.14V    1.071A     1.443A     829.5mA
-1.08V    754.2mA    1.168A     476.4mA
-1.02V    449mA      895.6mA    184.5mA
-960mV    195.8mA    625.5mA    36.73mA
-900mV    52.41mA    371.1mA    7.756mA
-840mV    10.72mA    170.2mA    4.398mA
-780mV    3.601mA    56.22mA    3.157mA
-720mV    2.062mA    15.03mA    2.179mA
-660mV    1.299mA    4.293mA    1.367mA
-360mV    5.029uA    27.47uA    1.319uA
3.96V     0A         0A         0A
[Ramp]
| variable   typ   min   max
dV/dt_r  0.6659/1.4845n   0.5099/2.4881n   0.8538/0.8509n
dV/dt_f  0.7256/1.5665n   0.5290/2.7488n   0.9327/0.8293n
R_load = 0.2330k
[Rising Waveform]
R_fixture= 0.2330k
V_fixture= 0.0
V_fixture_min= 0.0
V_fixture_max= 0.0
|time   V(typ)   V(min)   V(max)
0s        678.8pV    209.7nV    17.67pV
2.841ns   1.105mV    -10.47mV   15.75mV
4.029ns   1.526mV    1.226mV    1.123V
4.466ns   32.86mV    1.32mV     1.292V
5.06ns    284mV      235.4uV    1.371V
6.097ns   806.4mV    1.196mV    1.41V
7.637ns   1.045V     200.1mV    1.421V
9.379ns   1.095V     601.8mV    1.423V
10.94ns   1.106V     746.6mV    1.423V
18.55ns   1.11V      849.8mV    1.423V
[Rising Waveform]
R_fixture= 0.2330k
V_fixture= 1.8000
V_fixture_min= 1.7100
V_fixture_max= 1.9800
|time   V(typ)   V(min)   V(max)
0s        590.6mV    825.6mV    425.5mV
975.7ps   590.5mV    825.6mV    488.8mV
1.095ns   591.9mV    825.6mV    629.8mV
1.365ns   649.8mV    825.6mV    1.29V
1.626ns   932.7mV    826.8mV    1.611V
1.995ns   1.453V     878.9mV    1.807V
2.632ns   1.697V     1.381V     1.922V
3.17ns    1.756V     1.608V     1.961V
4.505ns   1.788V     1.691V     1.978V
18.55ns   1.8V       1.71V      1.98V
[Falling Waveform]
R_fixture= 0.2330k
V_fixture= 0.0
V_fixture_min= 0.0
V_fixture_max= 0.0
|time   V(typ)   V(min)   V(max)
0s        1.11V      851.8mV    1.423V
864.2ps   1.111V     851.7mV    1.343V
1.006ns   1.103V     851.7mV    1.16V
1.259ns   997.8mV    853.6mV    600.4mV
1.627ns   525.9mV    815mV      224.5mV
2.05ns    170.3mV    559.1mV    137.2mV
2.451ns   65.06mV    236.9mV    68.59mV
2.785ns   44.99mV    101.1mV    23.44mV
3.727ns   30.88mV    13.58mV    4.64mV
18.55ns   374.1nV    13.68uV    40.76nV
[Falling Waveform]
R_fixture= 0.2330k
V_fixture= 1.8000
V_fixture_min= 1.7100
V_fixture_max= 1.9800
|time   V(typ)   V(min)   V(max)
0s        1.8V       1.71V      1.98V
2.43ns    1.808V     1.729V     1.954V
2.741ns   1.81V      1.725V     1.739V
3.616ns   1.786V     1.713V     748.2mV
4.665ns   1.36V      1.715V     497.8mV
5.863ns   835.5mV    1.636V     445.8mV
7.322ns   665.6mV    1.295V     430.2mV
8.698ns   620.3mV    1.051V     426.7mV
10.49ns   600.1mV    912.3mV    425.7mV
18.55ns   590.7mV    828.4mV    425.5mV
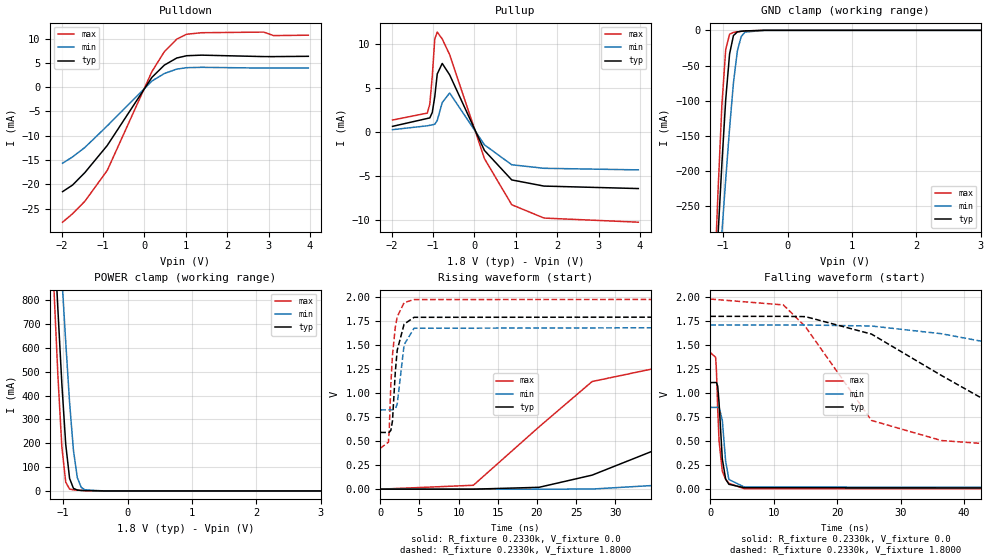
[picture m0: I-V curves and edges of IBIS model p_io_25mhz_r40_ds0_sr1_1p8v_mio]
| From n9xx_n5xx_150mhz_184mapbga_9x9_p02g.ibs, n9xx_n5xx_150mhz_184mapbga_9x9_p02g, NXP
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[Model] p_io_25mhz_r40_ds0_sr1_1p8v_mio
|   Model p_io_25mhz_r40_ds0_sr1_1p8v_mio
| This model was characterised for following simulation conditions:
| External (pad) voltage:
|   - Typ: 1.8V,   - Min: 1.71V,   - Max: 1.98V
| Library cells for typ/min/max conditions are connected as defined below:
|  pad - External Pad
|  ipp_do_lv - Core Input
|  ipp_obe_lv - Output Buffer Enable
|  IOGC - NC
|  REFH3V3 - REFH3V3
|  REFL3V3 - REFL3V3
|  ZI - NC
|  abut_ncal_vddio[1] - vssio vddio vddio
|  abut_ncal_vddio[2] - vddio vddio vssio
|  abut_ncal_vddio[3] - vddio
|  abut_ncal_vddio[4] - vssio vddio vddio
|  abut_ncal_vddio[5] - vddio vddio vssio
|  abut_ncal_vddio[6] - vddio
|  abut_pcal_vddio[1] - vssio
|  abut_pcal_vddio[2] - vddio vssio vddio
|  abut_pcal_vddio[3] - vssio
|  abut_pcal_vddio[4] - vssio
|  abut_pcal_vddio[5] - vddio vssio vddio
|  abut_pcal_vddio[6] - vssio
|  ipp_do_1p8v - ipp_do_1p8v
|  ipp_dse_lv - 0
|  ipp_eftd_lv - NC
|  ipp_ina_mux_vddio - NC
|  ipp_ina_mux_vddio[0] - NC
|  ipp_ina_mux_vddio[1] - NC
|  ipp_ina_r0_vddio - NC
|  ipp_ina_r0a_vddio - NC
|  ipp_ina_r0b_vddio - NC
|  ipp_ina_r0c_vddio - NC
|  ipp_ina_r0d_vddio - NC
|  ipp_ina_r0e_vddio - NC
|  ipp_ina_r0f_vddio - NC
|  ipp_ina_r300_vddio - NC
|  ipp_ina_r300a_vddio - NC
|  ipp_ina_r300b_vddio - NC
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Model_type I/O
Polarity   Non-Inverting
Enable   Active-High
Vinl =   0.5400V
Vinh =   1.2600V
Vmeas =  0.9000V
Cref =   30.0000pF
Rref =   1.0000M
Vref =   1.8000V
C_comp   1.7117pF   1.6504pF   1.7864pF
|C_comp_pullup   0.6284pF   0.6575pF   0.6017pF
|C_comp_pulldown   0.8222pF   0.8655pF   0.7891pF
[Model Spec]
| variable   typ   min   max
Vinh   1.2600V   1.1970V   1.3860V
Vinl   0.5400V   0.5130V   0.5940V
[Temperature Range]   25.0000   0.1250k   -40.0000
[Voltage Range]   1.8000V   1.7100V   1.9800V
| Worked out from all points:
|   slope of the pulldown table from 0 to 0.27 V, typ, clamps not added: 93.6 ohm
|   slope of the pullup table from 0 to 0.27 V, typ, clamps not added: 116 ohm
|   GND clamp passes 1 mA (typ) near -0.68 V on its own axis
|   POWER clamp passes 1 mA (typ) near -0.63 V on its own axis
|   rising waveform, R_fixture 0.2330k, V_fixture 0.0: 20-80 % time 23ns typ, 43.4ns min, 11.5ns max; typ from 0 V to 1.11 V
|   rising waveform, R_fixture 0.2330k, V_fixture 1.8000: 20-80 % time 711ps typ, 755ps min, 683ps max; typ from 0.591 V to 1.8 V
|   falling waveform, R_fixture 0.2330k, V_fixture 0.0: 20-80 % time 664ps typ, 736ps min, 624ps max; typ from 1.11 V to 0 V
|   falling waveform, R_fixture 0.2330k, V_fixture 1.8000: 20-80 % time 19.8ns typ, 38.6ns min, 9.8ns max; typ from 1.8 V to 0.591 V
[Pulldown]
|Voltage   I(typ)   I(min)   I(max)
-1.98V    -21.51mA   -15.67mA   -27.8mA
-1.74V    -20.17mA   -14.37mA   -26.07mA
-1.44V    -17.58mA   -12.41mA   -23.48mA
-900mV    -12.01mA   -7.971mA   -17.15mA
180mV     2.024mA    1.252mA    3.206mA
480mV     4.53mA     2.804mA    7.298mA
780mV     5.995mA    3.711mA    9.883mA
1.02V     6.465mA    4.004mA    10.89mA
1.38V     6.584mA    4.077mA    11.2mA
2.88V     6.288mA    3.92mA     11.33mA
3.12V     6.284mA    3.922mA    10.61mA
3.96V     6.345mA    3.956mA    10.69mA
[Pullup]
|Voltage   I(typ)   I(min)   I(max)
-1.98V    645.6uA    266.4uA    1.363mA
-1.14V    1.543mA    707.6uA    2.155mA
-1.08V    1.605mA    764.9uA    3.173mA
-1.02V    2.235mA    824.6uA    6.361mA
-960mV    4.023mA    885.7uA    10.59mA
-900mV    6.61mA     1.315mA    11.38mA
-780mV    7.81mA     3.355mA    10.6mA
-600mV    6.507mA    4.444mA    8.808mA
240mV     -2.097mA   -1.459mA   -3.023mA
900mV     -5.456mA   -3.727mA   -8.283mA
1.68V     -6.158mA   -4.133mA   -9.8mA
3.96V     -6.44mA    -4.311mA   -10.27mA
[GND_clamp]
|Voltage   I(typ)   I(min)   I(max)
-1.98V    -2.014A    -1.664A    -2.513A
-1.14V    -398mA     -446.7mA   -367.4mA
-1.08V    -291.8mA   -366.3mA   -229.6mA
-1.02V    -190.1mA   -287.6mA   -106.6mA
-960mV    -98.09mA   -211.4mA   -27.19mA
-900mV    -33.41mA   -139.1mA   -5.497mA
-840mV    -7.43mA    -74.57mA   -2.952mA
-780mV    -2.331mA   -29.72mA   -2.122mA
-720mV    -1.309mA   -8.82mA    -1.477mA
-660mV    -833.8uA   -2.501mA   -940.4uA
-360mV    -6.03uA    -22.55uA   -2.113uA
3.96V     0A         0A         0A
[POWER_clamp]
|Voltage   I(typ)   I(min)   I(max)
-1.98V    5.618A     5.349A     6.084A
-1.14V    1.071A     1.443A     829.6mA
-1.08V    754.2mA    1.168A     476.4mA
-1.02V    449mA      895.6mA    184.6mA
-960mV    195.8mA    625.5mA    36.79mA
-900mV    52.44mA    371.1mA    7.808mA
-840mV    10.74mA    170.2mA    4.435mA
-780mV    3.619mA    56.22mA    3.182mA
-720mV    2.074mA    15.04mA    2.195mA
-660mV    1.306mA    4.299mA    1.376mA
-360mV    5.079uA    27.62uA    1.341uA
3.96V     0A         0A         0A
[Ramp]
| variable   typ   min   max
dV/dt_r  0.6659/22.9578n   0.5083/43.3756n   0.8538/11.4878n
dV/dt_f  0.7254/19.8191n   0.5284/38.5927n   0.9326/9.8031n
R_load = 0.2330k
[Rising Waveform]
R_fixture= 0.2330k
V_fixture= 0.0
V_fixture_min= 0.0
V_fixture_max= 0.0
|time   V(typ)   V(min)   V(max)
0s        633.6pV    206nV      16.77pV
11.88ns   -32.91uV   -16.64uV   40.55mV
20.27ns   19.34mV    42.59uV    649mV
27.04ns   146.1mV    1.096mV    1.121V
40.16ns   571.5mV    63.95mV    1.345V
48.9ns    821.2mV    156.3mV    1.384V
58.89ns   958.9mV    289.1mV    1.404V
80.99ns   1.06V      579.7mV    1.419V
101.7ns   1.09V      719.4mV    1.422V
225.6ns   1.11V      847.1mV    1.423V
[Rising Waveform]
R_fixture= 0.2330k
V_fixture= 1.8000
V_fixture_min= 1.7100
V_fixture_max= 1.9800
|time   V(typ)   V(min)   V(max)
0s        590.8mV    825.8mV    425.7mV
1.037ns   590.8mV    825.9mV    489mV
1.136ns   590.9mV    825.9mV    597mV
1.35ns    612.5mV    825.9mV    1.092V
1.558ns   710.3mV    825.7mV    1.398V
1.919ns   1.221V     836.4mV    1.689V
2.164ns   1.448V     886.7mV    1.796V
3.044ns   1.719V     1.505V     1.943V
4.314ns   1.79V      1.676V     1.975V
225.6ns   1.8V       1.71V      1.98V
[Falling Waveform]
R_fixture= 0.2330k
V_fixture= 0.0
V_fixture_min= 0.0
V_fixture_max= 0.0
|time   V(typ)   V(min)   V(max)
0s        1.11V      851.8mV    1.423V
848.3ps   1.111V     851.8mV    1.373V
974.2ps   1.11V      851.8mV    1.233V
1.173ns   1.073V     852.4mV    828.1mV
1.388ns   897.7mV    853.3mV    501.4mV
1.892ns   317.3mV    718.7mV    187.8mV
2.422ns   105.5mV    292.2mV    103.3mV
2.932ns   50.8mV     100.8mV    61.57mV
5.327ns   15.28mV    23.3mV     5.153mV
225.6ns   203.3nV    2.919uV    51.82nV
[Falling Waveform]
R_fixture= 0.2330k
V_fixture= 1.8000
V_fixture_min= 1.7100
V_fixture_max= 1.9800
|time   V(typ)   V(min)   V(max)
0s        1.8V       1.71V      1.98V
11.52ns   1.8V       1.71V      1.919V
15ns      1.797V     1.71V      1.692V
25.42ns   1.615V     1.699V     715.4mV
36.44ns   1.184V     1.619V     506.5mV
44.18ns   896.2mV    1.523V     469.3mV
52.69ns   753.7mV    1.391V     449.5mV
72.78ns   648.4mV    1.083V     432.2mV
92.17ns   615.7mV    952.4mV    427.6mV
225.6ns   590.9mV    829.4mV    425.7mV
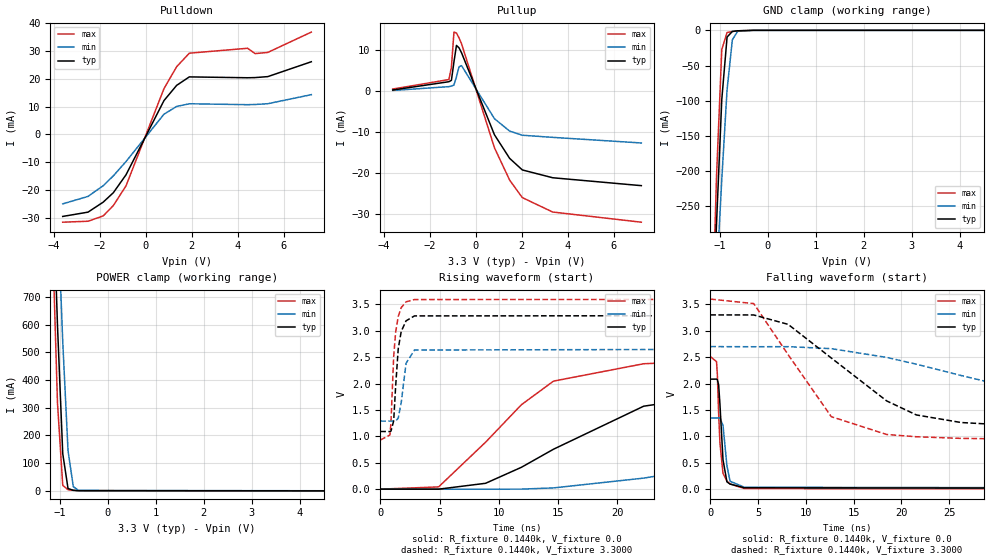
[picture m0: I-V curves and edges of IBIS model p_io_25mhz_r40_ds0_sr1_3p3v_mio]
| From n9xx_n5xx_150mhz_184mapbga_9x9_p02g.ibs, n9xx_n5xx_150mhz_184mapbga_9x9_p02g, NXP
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[Model] p_io_25mhz_r40_ds0_sr1_3p3v_mio
|   Model p_io_25mhz_r40_ds0_sr1_3p3v_mio
| This model was characterised for following simulation conditions:
| External (pad) voltage:
|   - Typ: 3.3V,   - Min: 2.7V,   - Max: 3.6V
| Library cells for typ/min/max conditions are connected as defined below:
|  pad - External Pad
|  ipp_do_lv - Core Input
|  ipp_obe_lv - Output Buffer Enable
|  IOGC - NC
|  REFH3V3 - REFH3V3
|  REFL3V3 - REFL3V3
|  ZI - NC
|  abut_ncal_vddio[1] - vddio
|  abut_ncal_vddio[2] - vddio
|  abut_ncal_vddio[3] - vssio
|  abut_ncal_vddio[4] - vddio
|  abut_ncal_vddio[5] - vddio
|  abut_ncal_vddio[6] - vssio
|  abut_pcal_vddio[1] - vssio
|  abut_pcal_vddio[2] - vssio
|  abut_pcal_vddio[3] - vddio
|  abut_pcal_vddio[4] - vssio
|  abut_pcal_vddio[5] - vssio
|  abut_pcal_vddio[6] - vddio
|  ipp_do_1p8v - ipp_do_1p8v
|  ipp_dse_lv - 0
|  ipp_eftd_lv - NC
|  ipp_ina_mux_vddio - NC
|  ipp_ina_mux_vddio[0] - NC
|  ipp_ina_mux_vddio[1] - NC
|  ipp_ina_r0_vddio - NC
|  ipp_ina_r0a_vddio - NC
|  ipp_ina_r0b_vddio - NC
|  ipp_ina_r0c_vddio - NC
|  ipp_ina_r0d_vddio - NC
|  ipp_ina_r0e_vddio - NC
|  ipp_ina_r0f_vddio - NC
|  ipp_ina_r300_vddio - NC
|  ipp_ina_r300a_vddio - NC
|  ipp_ina_r300b_vddio - NC
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Model_type I/O
Polarity   Non-Inverting
Enable   Active-High
Vinl =   0.9900V
Vinh =   2.3100V
Vmeas =  1.6500V
Cref =   30.0000pF
Rref =   1.0000M
Vref =   3.3000V
C_comp   1.6860pF   1.6265pF   1.7672pF
|C_comp_pullup   0.5966pF   0.6277pF   0.5754pF
|C_comp_pulldown   0.8289pF   0.8773pF   0.7913pF
[Model Spec]
| variable   typ   min   max
Vinh   2.3100V   1.8900V   2.5200V
Vinl   0.9900V   0.8100V   1.0800V
[Temperature Range]   25.0000   0.1250k   -40.0000
[Voltage Range]   3.3000V   2.7000V   3.6000V
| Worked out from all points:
|   slope of the pulldown table from 0 to 0.495 V, typ, clamps not added: 61.3 ohm
|   slope of the pullup table from 0 to 0.495 V, typ, clamps not added: 71.6 ohm
|   GND clamp passes 1 mA (typ) near -0.67 V on its own axis
|   POWER clamp passes 1 mA (typ) near -0.62 V on its own axis
|   rising waveform, R_fixture 0.1440k, V_fixture 0.0: 20-80 % time 11.8ns typ, 25.5ns min, 6.92ns max; typ from 0 V to 2.08 V
|   rising waveform, R_fixture 0.1440k, V_fixture 3.3000: 20-80 % time 436ps typ, 479ps min, 412ps max; typ from 1.09 V to 3.3 V
|   falling waveform, R_fixture 0.1440k, V_fixture 0.0: 20-80 % time 420ps typ, 480ps min, 394ps max; typ from 2.08 V to 0 V
|   falling waveform, R_fixture 0.1440k, V_fixture 3.3000: 20-80 % time 9.54ns typ, 20.9ns min, 5.75ns max; typ from 3.3 V to 1.09 V
[Pulldown]
|Voltage   I(typ)   I(min)   I(max)
-3.6V     -29.47mA   -24.96mA   -31.54mA
-2.5V     -27.93mA   -22.28mA   -31.2mA
-1.84V    -24.33mA   -18.43mA   -29.28mA
-1.4V     -20.95mA   -14.9mA    -25.56mA
-850mV    -14.52mA   -9.754mA   -18.49mA
800mV     12.14mA    7.26mA     16.44mA
1.35V     17.6mA     10.02mA    24.3mA
1.9V      20.64mA    10.99mA    29.15mA
4.43V     20.33mA    10.66mA    30.92mA
4.76V     20.39mA    10.73mA    29mA
5.31V     20.74mA    11.01mA    29.43mA
7.2V      26.08mA    14.26mA    36.73mA
[Pullup]
|Voltage   I(typ)   I(min)   I(max)
-3.6V     251.1uA    138.4uA    485.1uA
-1.16V    2.273mA    1.07mA     2.803mA
-1.05V    2.605mA    1.214mA    5.78mA
-940mV    7.098mA    1.466mA    14.39mA
-830mV    11.13mA    3.483mA    14.16mA
-720mV    10.55mA    5.906mA    12.99mA
-610mV    9.34mA     6.201mA    11.54mA
820mV     -10.68mA   -6.751mA   -13.85mA
1.48V     -16.44mA   -9.786mA   -21.76mA
2.03V     -19.26mA   -10.79mA   -26.02mA
3.35V     -21.17mA   -11.31mA   -29.54mA
7.2V      -23.1mA    -12.68mA   -32.02mA
[GND_clamp]
|Voltage   I(typ)   I(min)   I(max)
-3.6V     -5.343A    -4.159A    -6.913A
-1.18V    -470.5mA   -501mA     -462.9mA
-1.07V    -274.4mA   -353mA     -207.6mA
-960mV    -98.09mA   -211.4mA   -27.2mA
-850mV    -9.59mA    -84.32mA   -3.159mA
-740mV    -1.542mA   -13.52mA   -1.688mA
-630mV    -656uA     -1.44mA    -722.1uA
-300mV    -859.4nA   -5.611uA   -163.9nA
7.2V      0A         0A         0A
[POWER_clamp]
|Voltage   I(typ)   I(min)   I(max)
-3.6V     14.48A     12.95A     16.35A
-1.16V    1.177A     1.535A     951.2mA
-1.05V    598.4mA    1.032A     318mA
-940mV    134.2mA    537.3mA    20.05mA
-830mV    8.719mA    145.4mA    4.267mA
-720mV    2.135mA    15.38mA    2.236mA
-610mV    852.8uA    1.854mA    844.7uA
7.2V      0A         0A         0A
[Ramp]
| variable   typ   min   max
dV/dt_r  1.2494/11.7728n   0.8052/25.5429n   1.5064/6.9223n
dV/dt_f  1.3249/9.5395n   0.8445/20.9168n   1.6024/5.7459n
R_load = 0.1440k
[Rising Waveform]
R_fixture= 0.1440k
V_fixture= 0.0
V_fixture_min= 0.0
V_fixture_max= 0.0
|time   V(typ)   V(min)   V(max)
0s        4.64nV     156.5nV    15.82nV
4.924ns   -64.47uV   -250uV     42.71mV
8.889ns   111.1mV    2.877uV    889.6mV
11.91ns   413.8mV    689.8uV    1.599V
14.62ns   756.3mV    23.61mV    2.046V
22.23ns   1.571V     209mV      2.375V
32.45ns   1.912V     586.1mV    2.467V
44.24ns   2.014V     972.8mV    2.497V
56.18ns   2.052V     1.155V     2.506V
141ns     2.082V     1.342V     2.511V
[Rising Waveform]
R_fixture= 0.1440k
V_fixture= 3.3000
V_fixture_min= 2.7000
V_fixture_max= 3.6000
|time   V(typ)   V(min)   V(max)
0s        1.092V     1.289V     929.3mV
820.5ps   1.091V     1.289V     1.027V
903.9ps   1.1V       1.289V     1.276V
1.132ns   1.293V     1.289V     2.517V
1.296ns   1.944V     1.291V     2.97V
1.515ns   2.658V     1.343V     3.27V
1.768ns   2.987V     1.638V     3.439V
2.176ns   3.188V     2.384V     3.548V
2.885ns   3.281V     2.635V     3.591V
141ns     3.3V       2.7V       3.6V
[Falling Waveform]
R_fixture= 0.1440k
V_fixture= 0.0
V_fixture_min= 0.0
V_fixture_max= 0.0
|time   V(typ)   V(min)   V(max)
0s        2.083V     1.348V     2.511V
653.3ps   2.084V     1.348V     2.416V
738.9ps   2.075V     1.348V     2.175V
875.1ps   1.976V     1.349V     1.436V
1.01ns    1.615V     1.349V     879.7mV
1.332ns   556.4mV    1.207V     300.4mV
1.742ns   139.9mV    447mV      152.7mV
2.069ns   96.7mV     150.1mV    98.17mV
3.579ns   26.09mV    36.15mV    11.66mV
141ns     122nV      3.299uV    22.02nV
[Falling Waveform]
R_fixture= 0.1440k
V_fixture= 3.3000
V_fixture_min= 2.7000
V_fixture_max= 3.6000
|time   V(typ)   V(min)   V(max)
0s        3.3V       2.7V       3.6V
4.552ns   3.299V     2.697V     3.514V
8.149ns   3.121V     2.699V     2.547V
12.67ns   2.484V     2.661V     1.373V
18.47ns   1.671V     2.495V     1.035V
21.59ns   1.405V     2.366V     992.4mV
26.26ns   1.262V     2.152V     961.6mV
37.45ns   1.15V      1.672V     937.9mV
48.42ns   1.117V     1.472V     932.1mV
141ns     1.092V     1.293V     929.3mV
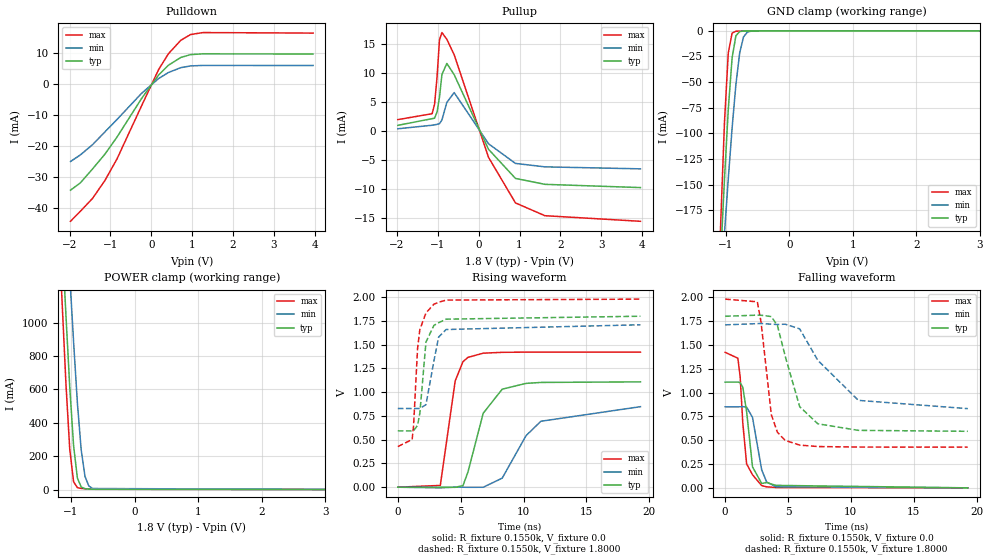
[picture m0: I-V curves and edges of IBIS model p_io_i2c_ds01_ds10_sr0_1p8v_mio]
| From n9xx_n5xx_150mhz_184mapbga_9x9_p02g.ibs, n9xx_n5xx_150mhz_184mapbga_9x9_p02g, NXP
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[Model] p_io_i2c_ds01_ds10_sr0_1p8v_mio
|   Model p_io_i2c_ds01_ds10_sr0_1p8v_mio
| This model was characterised for following simulation conditions:
| External (pad) voltage:
|   - Typ: 1.8V,   - Min: 1.71V,   - Max: 1.98V
| Library cells for typ/min/max conditions are connected as defined below:
|  pad - External Pad
|  ipp_do_lv - Core Input
|  ipp_obe_lv - Output Buffer Enable
|  IOGC - NC
|  REFH3V3 - REFH3V3
|  REFL3V3 - REFL3V3
|  ZI - NC
|  abut_ncal_vddio[1] - vssio vddio vddio
|  abut_ncal_vddio[2] - vddio vddio vssio
|  abut_ncal_vddio[3] - vddio
|  abut_ncal_vddio[4] - vssio vddio vddio
|  abut_ncal_vddio[5] - vddio vddio vssio
|  abut_ncal_vddio[6] - vddio
|  abut_pcal_vddio[1] - vssio
|  abut_pcal_vddio[2] - vddio vssio vddio
|  abut_pcal_vddio[3] - vssio
|  abut_pcal_vddio[4] - vssio
|  abut_pcal_vddio[5] - vddio vssio vddio
|  abut_pcal_vddio[6] - vssio
|  ipp_do_1p8v - ipp_do_1p8v
|  ipp_dse_lv[0] - vdd_lv
|  ipp_dse_lv[1] - 0
|  ipp_eftd_lv - NC
|  ipp_ina_mux_vddio - NC
|  ipp_ina_mux_vddio[0] - NC
|  ipp_ina_mux_vddio[1] - NC
|  ipp_ina_r0_vddio - NC
|  ipp_ina_r0a_vddio - NC
|  ipp_ina_r0b_vddio - NC
|  ipp_ina_r0c_vddio - NC
|  ipp_ina_r0d_vddio - NC
|  ipp_ina_r0e_vddio - NC
|  ipp_ina_r0f_vddio - NC
|  ipp_ina_r300_vddio - NC
|  ipp_ina_r300a_vddio - NC
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Model_type I/O
Polarity   Non-Inverting
Enable   Active-High
Vinl =   0.5400V
Vinh =   1.2600V
Vmeas =  0.9000V
Cref =   30.0000pF
Rref =   1.0000M
Vref =   1.8000V
C_comp   1.4328pF   1.3910pF   1.4871pF
|C_comp_pullup   0.6295pF   0.6727pF   0.5892pF
|C_comp_pulldown   0.7022pF   0.7083pF   0.7046pF
[Model Spec]
| variable   typ   min   max
Vinh   1.2600V   1.1970V   1.3860V
Vinl   0.5400V   0.5130V   0.5940V
[Temperature Range]   25.0000   0.1250k   -40.0000
[Voltage Range]   1.8000V   1.7100V   1.9800V
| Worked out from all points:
|   slope of the pulldown table from 0 to 0.27 V, typ, clamps not added: 62.5 ohm
|   slope of the pullup table from 0 to 0.27 V, typ, clamps not added: 77.5 ohm
|   GND clamp passes 1 mA (typ) near -0.78 V on its own axis
|   POWER clamp passes 1 mA (typ) near -0.58 V on its own axis
|   rising waveform, R_fixture 0.1550k, V_fixture 0.0: 20-80 % time 1.55ns typ, 2.53ns min, 876ps max; typ from 0 V to 1.11 V
|   rising waveform, R_fixture 0.1550k, V_fixture 1.8000: 20-80 % time 490ps typ, 582ps min, 480ps max; typ from 0.593 V to 1.8 V
|   falling waveform, R_fixture 0.1550k, V_fixture 0.0: 20-80 % time 536ps typ, 665ps min, 458ps max; typ from 1.11 V to 0 V
|   falling waveform, R_fixture 0.1550k, V_fixture 1.8000: 20-80 % time 1.53ns typ, 2.68ns min, 804ps max; typ from 1.8 V to 0.593 V
[Pulldown]
|Voltage   I(typ)   I(min)   I(max)
-1.98V    -34.2mA    -24.94mA   -44.24mA
-1.74V    -31.86mA   -22.83mA   -41.04mA
-1.44V    -27.34mA   -19.51mA   -36.85mA
-1.14V    -22.63mA   -15.42mA   -31.14mA
-840mV    -17.04mA   -11.36mA   -24.09mA
-240mV    -4.613mA   -2.936mA   -6.972mA
180mV     3.031mA    1.875mA    4.796mA
420mV     6.16mA     3.813mA    9.881mA
720mV     8.658mA    5.36mA     14.2mA
960mV     9.581mA    5.932mA    16.06mA
1.26V     9.826mA    6.085mA    16.7mA
3.96V     9.775mA    6.071mA    16.53mA
[Pullup]
|Voltage   I(typ)   I(min)   I(max)
-1.98V    993.6uA    401.3uA    1.989mA
-1.14V    2.152mA    1.013mA    3.004mA
-1.08V    2.231mA    1.087mA    4.647mA
-1.02V    3.272mA    1.164mA    9.289mA
-960mV    5.867mA    1.291mA    15.78mA
-900mV    9.784mA    1.928mA    17.04mA
-780mV    11.7mA     4.959mA    15.88mA
-600mV    9.753mA    6.662mA    13.2mA
240mV     -3.145mA   -2.189mA   -4.532mA
900mV     -8.182mA   -5.59mA    -12.42mA
1.62V     -9.207mA   -6.184mA   -14.63mA
3.96V     -9.769mA   -6.528mA   -15.6mA
[GND_clamp]
|Voltage   I(typ)   I(min)   I(max)
-1.98V    -1.586A    -1.229A    -2.1A
-1.08V    -221.4mA   -253.6mA   -188.5mA
-1.02V    -144.6mA   -197.7mA   -89.32mA
-960mV    -76.59mA   -144.3mA   -21.58mA
-900mV    -26.43mA   -94.89mA   -2.183mA
-840mV    -4.754mA   -52.29mA   -428.7uA
-780mV    -708.9uA   -21.31mA   -240uA
-720mV    -194.5uA   -5.864mA   -159.9uA
-660mV    -97.62uA   -1.274mA   -100.6uA
-600mV    -55.49uA   -286.4uA   -56.47uA
-420mV    -4.265uA   -10.7uA    -2.74uA
3.96V     0A         0A         0A
[POWER_clamp]
|Voltage   I(typ)   I(min)   I(max)
-1.98V    7.929A     7.752A     8.366A
-1.2V     1.949A     2.483A     1.628A
-1.14V    1.495A     2.081A     1.12A
-1.08V    1.044A     1.68A      633.7mA
-1.02V    613.2mA    1.282A     240.4mA
-960mV    264mA      886.2mA    47.43mA
-900mV    69.94mA    519.6mA    11.58mA
-840mV    15.1mA     237.3mA    7.049mA
-780mV    5.589mA    78.54mA    5.099mA
-720mV    3.316mA    21.56mA    3.521mA
-660mV    2.102mA    6.487mA    2.205mA
3.96V     0A         0A         0A
[Ramp]
| variable   typ   min   max
dV/dt_r  0.6651/1.5497n   0.5087/2.5339n   0.8530/0.8759n
dV/dt_f  0.7240/1.5261n   0.5273/2.6752n   0.9315/0.8041n
R_load = 0.1550k
[Rising Waveform]
R_fixture= 0.1550k
V_fixture= 0.0
V_fixture_min= 0.0
V_fixture_max= 0.0
|time   V(typ)   V(min)   V(max)
0s        511.6pV    206.6nV    17.81pV
3.381ns   -73.79uV   -6.875mV   18.92mV
4.565ns   -1.056mV   792.5uV    1.12V
5.183ns   16.46mV    -38.67uV   1.322V
5.583ns   161.5mV    -1.071mV   1.367V
6.792ns   778.5mV    -650.3uV   1.411V
8.304ns   1.032V     95.61mV    1.42V
10.2ns    1.093V     542.7mV    1.422V
11.38ns   1.103V     694.3mV    1.422V
19.3ns    1.109V     847.9mV    1.422V
[Rising Waveform]
R_fixture= 0.1550k
V_fixture= 1.8000
V_fixture_min= 1.7100
V_fixture_max= 1.9800
|time   V(typ)   V(min)   V(max)
0s        593mV      828.3mV    427.5mV
1.14ns    592.7mV    828.3mV    502mV
1.255ns   594.5mV    828.3mV    650.5mV
1.572ns   651.8mV    828.2mV    1.461V
1.751ns   778mV      828.2mV    1.658V
2.239ns   1.528V     869.6mV    1.835V
2.873ns   1.704V     1.329V     1.927V
3.246ns   1.732V     1.58V      1.947V
3.843ns   1.769V     1.66V      1.97V
19.3ns    1.8V       1.71V      1.98V
[Falling Waveform]
R_fixture= 0.1550k
V_fixture= 0.0
V_fixture_min= 0.0
V_fixture_max= 0.0
|time   V(typ)   V(min)   V(max)
0s        1.109V     850.5mV    1.422V
1.01ns    1.11V      850.4mV    1.36V
1.191ns   1.103V     850.7mV    1.167V
1.402ns   1.056V     852mV      681mV
1.706ns   800mV      846.4mV    251.4mV
2.174ns   220.7mV    739.2mV    137.5mV
2.905ns   45.93mV    189mV      23.62mV
3.305ns   56.04mV    60.06mV    10.54mV
4.03ns    26.01mV    12.08mV    4.072mV
19.3ns    3.689uV    37.02uV    294.8nV
[Falling Waveform]
R_fixture= 0.1550k
V_fixture= 1.8000
V_fixture_min= 1.7100
V_fixture_max= 1.9800
|time   V(typ)   V(min)   V(max)
0s        1.8V       1.71V      1.98V
2.558ns   1.812V     1.723V     1.952V
2.854ns   1.811V     1.725V     1.739V
3.668ns   1.797V     1.717V     769.6mV
4.156ns   1.704V     1.714V     582.5mV
4.775ns   1.382V     1.717V     498.2mV
5.926ns   851.9mV    1.668V     448.7mV
7.369ns   672mV      1.338V     433.4mV
10.6ns    603.2mV    917.7mV    428mV
19.3ns    593.3mV    831.1mV    427.5mV
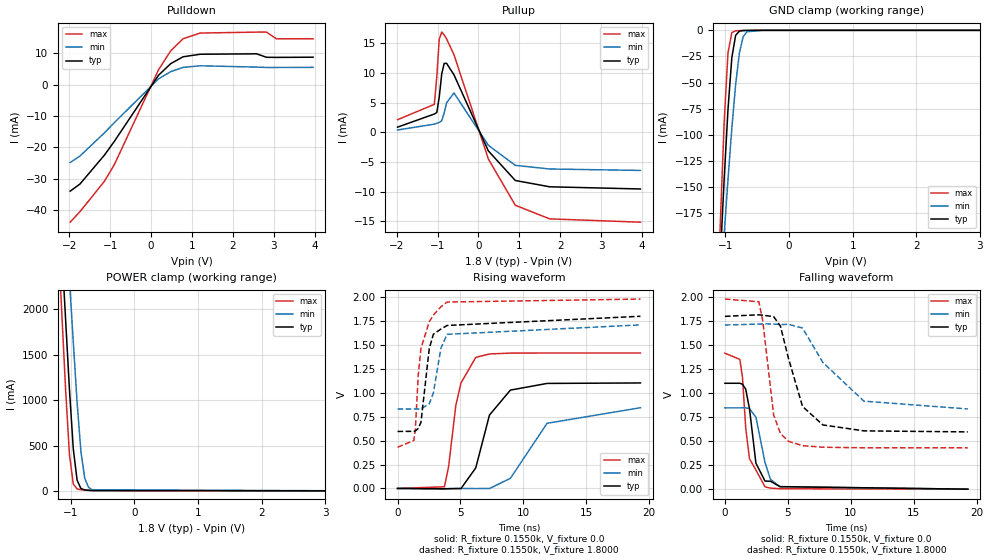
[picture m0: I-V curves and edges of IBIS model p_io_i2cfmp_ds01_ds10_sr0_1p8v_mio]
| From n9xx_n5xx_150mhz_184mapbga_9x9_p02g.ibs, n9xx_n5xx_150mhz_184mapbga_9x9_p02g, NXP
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[Model] p_io_i2cfmp_ds01_ds10_sr0_1p8v_mio
|   Model p_io_i2cfmp_ds01_ds10_sr0_1p8v_mio
| This model was characterised for following simulation conditions:
| External (pad) voltage:
|   - Typ: 1.8V,   - Min: 1.71V,   - Max: 1.98V
| Library cells for typ/min/max conditions are connected as defined below:
|  pad - External Pad
|  ipp_do_lv - Core Input
|  ipp_obe_lv - Output Buffer Enable
|  IOGC - NC
|  REFH3V3 - REFH3V3
|  REFL3V3 - REFL3V3
|  ZI - NC
|  abut_ncal_vddio[1] - vssio vddio vddio
|  abut_ncal_vddio[2] - vddio vddio vssio
|  abut_ncal_vddio[3] - vddio
|  abut_ncal_vddio[4] - vssio vddio vddio
|  abut_ncal_vddio[5] - vddio vddio vssio
|  abut_ncal_vddio[6] - vddio
|  abut_pcal_vddio[1] - vssio
|  abut_pcal_vddio[2] - vddio vssio vddio
|  abut_pcal_vddio[3] - vssio
|  abut_pcal_vddio[4] - vssio
|  abut_pcal_vddio[5] - vddio vssio vddio
|  abut_pcal_vddio[6] - vssio
|  ipp_do_1p8v - ipp_do_1p8v
|  ipp_dse_lv[0] - vdd_lv
|  ipp_dse_lv[1] - 0
|  ipp_eftd_lv - NC
|  ipp_ina_mux_vddio - NC
|  ipp_ina_mux_vddio[0] - NC
|  ipp_ina_mux_vddio[1] - NC
|  ipp_ina_r0_vddio - NC
|  ipp_ina_r0a_vddio - NC
|  ipp_ina_r0b_vddio - NC
|  ipp_ina_r0c_vddio - NC
|  ipp_ina_r0d_vddio - NC
|  ipp_ina_r0e_vddio - NC
|  ipp_ina_r0f_vddio - NC
|  ipp_ina_r300_vddio - NC
|  ipp_ina_r300a_vddio - NC
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Model_type I/O
Polarity   Non-Inverting
Enable   Active-High
Vinl =   0.5400V
Vinh =   1.2600V
Vmeas =  0.9000V
Cref =   30.0000pF
Rref =   1.0000M
Vref =   1.8000V
C_comp   1.7515pF   1.7218pF   1.7928pF
|C_comp_pullup   0.7565pF   0.8220pF   0.7002pF
|C_comp_pulldown   0.8811pF   0.8518pF   0.9104pF
[Model Spec]
| variable   typ   min   max
Vinh   1.2600V   1.1970V   1.3860V
Vinl   0.5400V   0.5130V   0.5940V
[Temperature Range]   25.0000   0.1250k   -40.0000
[Voltage Range]   1.8000V   1.7100V   1.9800V
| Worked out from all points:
|   slope of the pulldown table from 0 to 0.27 V, typ, clamps not added: 62.9 ohm
|   slope of the pullup table from 0 to 0.27 V, typ, clamps not added: 78.2 ohm
|   GND clamp passes 1 mA (typ) near -0.78 V on its own axis
|   POWER clamp passes 1 mA (typ) near -0.53 V on its own axis
|   rising waveform, R_fixture 0.1550k, V_fixture 0.0: 20-80 % time 1.68ns typ, 2.55ns min, 983ps max; typ from 0 V to 1.1 V
|   rising waveform, R_fixture 0.1550k, V_fixture 1.8000: 20-80 % time 656ps typ, 743ps min, 744ps max; typ from 0.596 V to 1.8 V
|   falling waveform, R_fixture 0.1550k, V_fixture 0.0: 20-80 % time 645ps typ, 768ps min, 608ps max; typ from 1.1 V to 0 V
|   falling waveform, R_fixture 0.1550k, V_fixture 1.8000: 20-80 % time 1.55ns typ, 2.65ns min, 847ps max; typ from 1.8 V to 0.596 V
[Pulldown]
|Voltage   I(typ)   I(min)   I(max)
-1.98V    -34.04mA   -24.87mA   -43.96mA
-1.74V    -31.75mA   -22.8mA    -40.58mA
-1.14V    -22.47mA   -15.36mA   -30.83mA
-900mV    -18.11mA   -12.15mA   -25.55mA
180mV     3.015mA    1.868mA    4.762mA
480mV     6.746mA    4.184mA    10.85mA
780mV     8.923mA    5.533mA    14.69mA
1.2V      9.737mA    6.042mA    16.51mA
2.58V     9.872mA    5.631mA    16.81mA
2.82V     8.763mA    5.508mA    16.82mA
3.06V     8.728mA    5.506mA    14.68mA
3.96V     8.792mA    5.545mA    14.66mA
[Pullup]
|Voltage   I(typ)   I(min)   I(max)
-1.98V    874.2uA    394.3uA    2.123mA
-1.08V    3.084mA    1.378mA    4.713mA
-1.02V    3.333mA    1.519mA    9.342mA
-960mV    5.93mA     1.665mA    15.68mA
-900mV    9.793mA    1.958mA    16.88mA
-840mV    11.6mA     3.244mA    16.41mA
-780mV    11.62mA    4.985mA    15.73mA
-600mV    9.684mA    6.632mA    13.07mA
240mV     -3.119mA   -2.177mA   -4.482mA
900mV     -8.107mA   -5.556mA   -12.28mA
1.74V     -9.17mA    -6.172mA   -14.57mA
3.96V     -9.537mA   -6.417mA   -15.13mA
[GND_clamp]
|Voltage   I(typ)   I(min)   I(max)
-1.98V    -1.571A    -1.243A    -2.046A
-1.14V    -296.8mA   -307.7mA   -291.9mA
-1.08V    -217.1mA   -250.6mA   -183.3mA
-1.02V    -142mA     -195.3mA   -87.29mA
-960mV    -75.42mA   -142.6mA   -21.4mA
-900mV    -26.21mA   -93.87mA   -2.23mA
-840mV    -4.776mA   -51.84mA   -446.5uA
-780mV    -725.4uA   -21.22mA   -243.9uA
-720mV    -200uA     -5.88mA    -159.3uA
-660mV    -98.47uA   -1.291mA   -98.82uA
-420mV    -3.926uA   -10.95uA   -2.45uA
3.96V     0A         0A         0A
[POWER_clamp]
|Voltage   I(typ)   I(min)   I(max)
-1.98V    13.51A     13.25A     14.01A
-1.2V     3.414A     4.356A     2.802A
-1.14V    2.644A     3.675A     1.949A
-1.08V    1.876A     2.995A     1.103A
-1.02V    1.113A     2.317A     397.9mA
-960mV    462.1mA    1.641A     75.38mA
-900mV    117mA      972.3mA    21.31mA
-840mV    26.38mA    432.6mA    13.76mA
-780mV    10.65mA    139.4mA    9.996mA
-720mV    6.506mA    38.48mA    6.892mA
-660mV    4.142mA    12.01mA    4.303mA
3.96V     0A         0A         0A
[Ramp]
| variable   typ   min   max
dV/dt_r  0.6621/1.6841n   0.5063/2.5460n   0.8497/0.9833n
dV/dt_f  0.7221/1.5535n   0.5248/2.6500n   0.9298/0.8469n
R_load = 0.1550k
[Rising Waveform]
R_fixture= 0.1550k
V_fixture= 0.0
V_fixture_min= 0.0
V_fixture_max= 0.0
|time   V(typ)   V(min)   V(max)
0s        874.6pV    404.1nV    21.73pV
3.726ns   -2.867mV   -7.548mV   17.64mV
4.062ns   -2.318mV   -2.782mV   231.2mV
4.629ns   -1.597mV   -319.2uV   865.9mV
5.041ns   -1.162mV   -376uV     1.103V
6.215ns   215mV      -1.178mV   1.37V
7.306ns   767.5mV    -769.1uV   1.406V
8.966ns   1.028V     105.7mV    1.415V
11.88ns   1.098V     681.2mV    1.416V
19.3ns    1.103V     843.8mV    1.416V
[Rising Waveform]
R_fixture= 0.1550k
V_fixture= 1.8000
V_fixture_min= 1.7100
V_fixture_max= 1.9800
|time   V(typ)   V(min)   V(max)
0s        596mV      831.1mV    430.4mV
1.291ns   597mV      831.1mV    501.4mV
1.417ns   601.2mV    831.1mV    619mV
1.646ns   627.3mV    830.9mV    1.188V
1.863ns   692.7mV    831.8mV    1.465V
2.522ns   1.463V     884.9mV    1.742V
2.848ns   1.612V     1V         1.813V
3.444ns   1.666V     1.465V     1.899V
3.938ns   1.704V     1.611V     1.949V
19.3ns    1.8V       1.71V      1.98V
[Falling Waveform]
R_fixture= 0.1550k
V_fixture= 0.0
V_fixture_min= 0.0
V_fixture_max= 0.0
|time   V(typ)   V(min)   V(max)
0s        1.103V     846.9mV    1.416V
1.19ns    1.103V     846.6mV    1.352V
1.4ns     1.092V     847.4mV    1.161V
1.654ns   1.042V     847.6mV    638.1mV
1.956ns   836.4mV    838.2mV    316.5mV
2.465ns   270mV      750.4mV    198.8mV
3.19ns    84.59mV    276.8mV    24.54mV
3.62ns    82.59mV    102.2mV    10.79mV
4.374ns   26.47mV    25.63mV    4.364mV
19.3ns    4.33uV     52.44uV    267.3nV
[Falling Waveform]
R_fixture= 0.1550k
V_fixture= 1.8000
V_fixture_min= 1.7100
V_fixture_max= 1.9800
|time   V(typ)   V(min)   V(max)
0s        1.8V       1.71V      1.98V
2.701ns   1.816V     1.719V     1.952V
3.007ns   1.812V     1.722V     1.754V
3.876ns   1.797V     1.72V      771.8mV
4.413ns   1.698V     1.714V     579.7mV
5.047ns   1.365V     1.717V     498.7mV
6.167ns   862mV      1.678V     453.1mV
7.787ns   669mV      1.319V     436.6mV
11.05ns   607.1mV    916.7mV    430.9mV
19.3ns    596.5mV    835.4mV    430.4mV
